VERSION 5.8 ;
BUSBITCHARS "[]" ;
DIVIDERCHAR "/" ;
UNITS
    DATABASE MICRONS 1000 ;
END UNITS

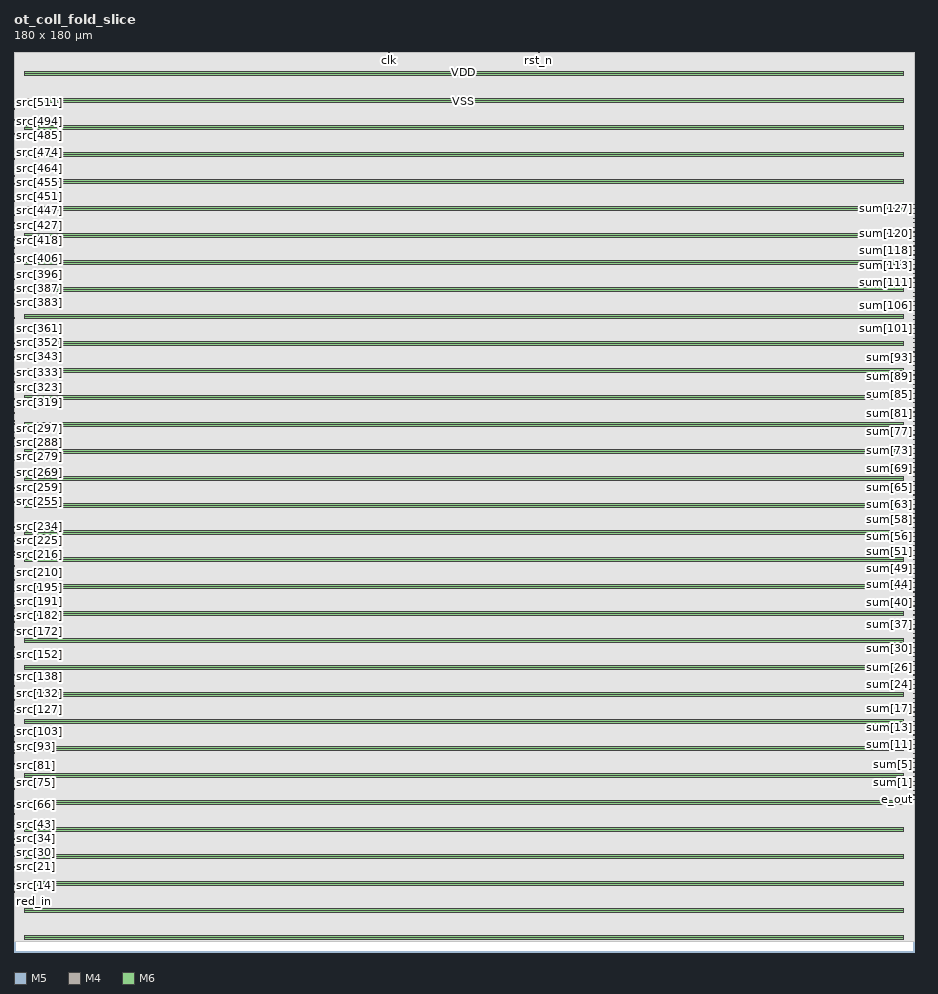
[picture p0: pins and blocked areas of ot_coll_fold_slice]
MACRO ot_coll_fold_slice
  FOREIGN ot_coll_fold_slice 0 0 ;
  CLASS BLOCK ;
  SIZE 180 BY 180 ;
  PIN clk
    DIRECTION INPUT ;
    USE SIGNAL ;
    PORT
      LAYER M5 ;
        RECT  74.976 179.916 75 180 ;
    END
  END clk
  PIN e_out
    DIRECTION OUTPUT ;
    USE SIGNAL ;
    PORT
      LAYER M4 ;
        RECT  179.916 30.432 180 30.456 ;
    END
  END e_out
  PIN red_in
    DIRECTION INPUT ;
    USE SIGNAL ;
    PORT
      LAYER M4 ;
        RECT  0 10.128 0.084 10.152 ;
    END
  END red_in
  PIN rst_n
    DIRECTION INPUT ;
    USE SIGNAL ;
    PORT
      LAYER M5 ;
        RECT  104.976 179.916 105 180 ;
    END
  END rst_n
  PIN src[0]
    DIRECTION INPUT ;
    USE SIGNAL ;
    PORT
      LAYER M4 ;
        RECT  0 10.464 0.084 10.488 ;
    END
  END src[0]
  PIN src[100]
    DIRECTION INPUT ;
    USE SIGNAL ;
    PORT
      LAYER M6 ;
        RECT  0 41.664 0.07 41.696 ;
    END
  END src[100]
  PIN src[101]
    DIRECTION INPUT ;
    USE SIGNAL ;
    PORT
      LAYER M6 ;
        RECT  0 41.984 0.07 42.016 ;
    END
  END src[101]
  PIN src[102]
    DIRECTION INPUT ;
    USE SIGNAL ;
    PORT
      LAYER M6 ;
        RECT  0 42.24 0.07 42.272 ;
    END
  END src[102]
  PIN src[103]
    DIRECTION INPUT ;
    USE SIGNAL ;
    PORT
      LAYER M6 ;
        RECT  0 42.56 0.07 42.592 ;
    END
  END src[103]
  PIN src[104]
    DIRECTION INPUT ;
    USE SIGNAL ;
    PORT
      LAYER M6 ;
        RECT  0 42.88 0.07 42.912 ;
    END
  END src[104]
  PIN src[105]
    DIRECTION INPUT ;
    USE SIGNAL ;
    PORT
      LAYER M6 ;
        RECT  0 43.2 0.07 43.232 ;
    END
  END src[105]
  PIN src[106]
    DIRECTION INPUT ;
    USE SIGNAL ;
    PORT
      LAYER M6 ;
        RECT  0 43.52 0.07 43.552 ;
    END
  END src[106]
  PIN src[107]
    DIRECTION INPUT ;
    USE SIGNAL ;
    PORT
      LAYER M6 ;
        RECT  0 43.84 0.07 43.872 ;
    END
  END src[107]
  PIN src[108]
    DIRECTION INPUT ;
    USE SIGNAL ;
    PORT
      LAYER M6 ;
        RECT  0 44.16 0.07 44.192 ;
    END
  END src[108]
  PIN src[109]
    DIRECTION INPUT ;
    USE SIGNAL ;
    PORT
      LAYER M6 ;
        RECT  0 44.48 0.07 44.512 ;
    END
  END src[109]
  PIN src[10]
    DIRECTION INPUT ;
    USE SIGNAL ;
    PORT
      LAYER M4 ;
        RECT  0 13.584 0.084 13.608 ;
    END
  END src[10]
  PIN src[110]
    DIRECTION INPUT ;
    USE SIGNAL ;
    PORT
      LAYER M6 ;
        RECT  0 44.736 0.07 44.768 ;
    END
  END src[110]
  PIN src[111]
    DIRECTION INPUT ;
    USE SIGNAL ;
    PORT
      LAYER M6 ;
        RECT  0 45.056 0.07 45.088 ;
    END
  END src[111]
  PIN src[112]
    DIRECTION INPUT ;
    USE SIGNAL ;
    PORT
      LAYER M6 ;
        RECT  0 45.376 0.07 45.408 ;
    END
  END src[112]
  PIN src[113]
    DIRECTION INPUT ;
    USE SIGNAL ;
    PORT
      LAYER M6 ;
        RECT  0 45.696 0.07 45.728 ;
    END
  END src[113]
  PIN src[114]
    DIRECTION INPUT ;
    USE SIGNAL ;
    PORT
      LAYER M6 ;
        RECT  0 46.016 0.07 46.048 ;
    END
  END src[114]
  PIN src[115]
    DIRECTION INPUT ;
    USE SIGNAL ;
    PORT
      LAYER M6 ;
        RECT  0 46.336 0.07 46.368 ;
    END
  END src[115]
  PIN src[116]
    DIRECTION INPUT ;
    USE SIGNAL ;
    PORT
      LAYER M6 ;
        RECT  0 46.656 0.07 46.688 ;
    END
  END src[116]
  PIN src[117]
    DIRECTION INPUT ;
    USE SIGNAL ;
    PORT
      LAYER M6 ;
        RECT  0 46.912 0.07 46.944 ;
    END
  END src[117]
  PIN src[118]
    DIRECTION INPUT ;
    USE SIGNAL ;
    PORT
      LAYER M6 ;
        RECT  0 47.232 0.07 47.264 ;
    END
  END src[118]
  PIN src[119]
    DIRECTION INPUT ;
    USE SIGNAL ;
    PORT
      LAYER M6 ;
        RECT  0 47.552 0.07 47.584 ;
    END
  END src[119]
  PIN src[11]
    DIRECTION INPUT ;
    USE SIGNAL ;
    PORT
      LAYER M4 ;
        RECT  0 13.872 0.084 13.896 ;
    END
  END src[11]
  PIN src[120]
    DIRECTION INPUT ;
    USE SIGNAL ;
    PORT
      LAYER M6 ;
        RECT  0 47.872 0.07 47.904 ;
    END
  END src[120]
  PIN src[121]
    DIRECTION INPUT ;
    USE SIGNAL ;
    PORT
      LAYER M6 ;
        RECT  0 48.192 0.07 48.224 ;
    END
  END src[121]
  PIN src[122]
    DIRECTION INPUT ;
    USE SIGNAL ;
    PORT
      LAYER M6 ;
        RECT  0 48.512 0.07 48.544 ;
    END
  END src[122]
  PIN src[123]
    DIRECTION INPUT ;
    USE SIGNAL ;
    PORT
      LAYER M6 ;
        RECT  0 48.832 0.07 48.864 ;
    END
  END src[123]
  PIN src[124]
    DIRECTION INPUT ;
    USE SIGNAL ;
    PORT
      LAYER M6 ;
        RECT  0 49.152 0.07 49.184 ;
    END
  END src[124]
  PIN src[125]
    DIRECTION INPUT ;
    USE SIGNAL ;
    PORT
      LAYER M6 ;
        RECT  0 49.408 0.07 49.44 ;
    END
  END src[125]
  PIN src[126]
    DIRECTION INPUT ;
    USE SIGNAL ;
    PORT
      LAYER M6 ;
        RECT  0 49.728 0.07 49.76 ;
    END
  END src[126]
  PIN src[127]
    DIRECTION INPUT ;
    USE SIGNAL ;
    PORT
      LAYER M4 ;
        RECT  0 50.064 0.084 50.088 ;
    END
  END src[127]
  PIN src[128]
    DIRECTION INPUT ;
    USE SIGNAL ;
    PORT
      LAYER M4 ;
        RECT  0 50.4 0.084 50.424 ;
    END
  END src[128]
  PIN src[129]
    DIRECTION INPUT ;
    USE SIGNAL ;
    PORT
      LAYER M4 ;
        RECT  0 50.688 0.084 50.712 ;
    END
  END src[129]
  PIN src[12]
    DIRECTION INPUT ;
    USE SIGNAL ;
    PORT
      LAYER M4 ;
        RECT  0 14.208 0.084 14.232 ;
    END
  END src[12]
  PIN src[130]
    DIRECTION INPUT ;
    USE SIGNAL ;
    PORT
      LAYER M4 ;
        RECT  0 51.024 0.084 51.048 ;
    END
  END src[130]
  PIN src[131]
    DIRECTION INPUT ;
    USE SIGNAL ;
    PORT
      LAYER M4 ;
        RECT  0 51.312 0.084 51.336 ;
    END
  END src[131]
  PIN src[132]
    DIRECTION INPUT ;
    USE SIGNAL ;
    PORT
      LAYER M4 ;
        RECT  0 51.648 0.084 51.672 ;
    END
  END src[132]
  PIN src[133]
    DIRECTION INPUT ;
    USE SIGNAL ;
    PORT
      LAYER M4 ;
        RECT  0 51.936 0.084 51.96 ;
    END
  END src[133]
  PIN src[134]
    DIRECTION INPUT ;
    USE SIGNAL ;
    PORT
      LAYER M4 ;
        RECT  0 52.272 0.084 52.296 ;
    END
  END src[134]
  PIN src[135]
    DIRECTION INPUT ;
    USE SIGNAL ;
    PORT
      LAYER M4 ;
        RECT  0 52.56 0.084 52.584 ;
    END
  END src[135]
  PIN src[136]
    DIRECTION INPUT ;
    USE SIGNAL ;
    PORT
      LAYER M4 ;
        RECT  0 52.896 0.084 52.92 ;
    END
  END src[136]
  PIN src[137]
    DIRECTION INPUT ;
    USE SIGNAL ;
    PORT
      LAYER M4 ;
        RECT  0 53.184 0.084 53.208 ;
    END
  END src[137]
  PIN src[138]
    DIRECTION INPUT ;
    USE SIGNAL ;
    PORT
      LAYER M4 ;
        RECT  0 53.52 0.084 53.544 ;
    END
  END src[138]
  PIN src[139]
    DIRECTION INPUT ;
    USE SIGNAL ;
    PORT
      LAYER M4 ;
        RECT  0 53.808 0.084 53.832 ;
    END
  END src[139]
  PIN src[13]
    DIRECTION INPUT ;
    USE SIGNAL ;
    PORT
      LAYER M4 ;
        RECT  0 14.496 0.084 14.52 ;
    END
  END src[13]
  PIN src[140]
    DIRECTION INPUT ;
    USE SIGNAL ;
    PORT
      LAYER M4 ;
        RECT  0 54.144 0.084 54.168 ;
    END
  END src[140]
  PIN src[141]
    DIRECTION INPUT ;
    USE SIGNAL ;
    PORT
      LAYER M4 ;
        RECT  0 54.432 0.084 54.456 ;
    END
  END src[141]
  PIN src[142]
    DIRECTION INPUT ;
    USE SIGNAL ;
    PORT
      LAYER M4 ;
        RECT  0 54.768 0.084 54.792 ;
    END
  END src[142]
  PIN src[143]
    DIRECTION INPUT ;
    USE SIGNAL ;
    PORT
      LAYER M4 ;
        RECT  0 55.056 0.084 55.08 ;
    END
  END src[143]
  PIN src[144]
    DIRECTION INPUT ;
    USE SIGNAL ;
    PORT
      LAYER M4 ;
        RECT  0 55.392 0.084 55.416 ;
    END
  END src[144]
  PIN src[145]
    DIRECTION INPUT ;
    USE SIGNAL ;
    PORT
      LAYER M4 ;
        RECT  0 55.68 0.084 55.704 ;
    END
  END src[145]
  PIN src[146]
    DIRECTION INPUT ;
    USE SIGNAL ;
    PORT
      LAYER M4 ;
        RECT  0 56.016 0.084 56.04 ;
    END
  END src[146]
  PIN src[147]
    DIRECTION INPUT ;
    USE SIGNAL ;
    PORT
      LAYER M4 ;
        RECT  0 56.304 0.084 56.328 ;
    END
  END src[147]
  PIN src[148]
    DIRECTION INPUT ;
    USE SIGNAL ;
    PORT
      LAYER M4 ;
        RECT  0 56.64 0.084 56.664 ;
    END
  END src[148]
  PIN src[149]
    DIRECTION INPUT ;
    USE SIGNAL ;
    PORT
      LAYER M4 ;
        RECT  0 56.928 0.084 56.952 ;
    END
  END src[149]
  PIN src[14]
    DIRECTION INPUT ;
    USE SIGNAL ;
    PORT
      LAYER M4 ;
        RECT  0 14.832 0.084 14.856 ;
    END
  END src[14]
  PIN src[150]
    DIRECTION INPUT ;
    USE SIGNAL ;
    PORT
      LAYER M4 ;
        RECT  0 57.216 0.084 57.24 ;
    END
  END src[150]
  PIN src[151]
    DIRECTION INPUT ;
    USE SIGNAL ;
    PORT
      LAYER M4 ;
        RECT  0 57.552 0.084 57.576 ;
    END
  END src[151]
  PIN src[152]
    DIRECTION INPUT ;
    USE SIGNAL ;
    PORT
      LAYER M4 ;
        RECT  0 57.84 0.084 57.864 ;
    END
  END src[152]
  PIN src[153]
    DIRECTION INPUT ;
    USE SIGNAL ;
    PORT
      LAYER M4 ;
        RECT  0 58.176 0.084 58.2 ;
    END
  END src[153]
  PIN src[154]
    DIRECTION INPUT ;
    USE SIGNAL ;
    PORT
      LAYER M4 ;
        RECT  0 58.464 0.084 58.488 ;
    END
  END src[154]
  PIN src[155]
    DIRECTION INPUT ;
    USE SIGNAL ;
    PORT
      LAYER M4 ;
        RECT  0 58.8 0.084 58.824 ;
    END
  END src[155]
  PIN src[156]
    DIRECTION INPUT ;
    USE SIGNAL ;
    PORT
      LAYER M4 ;
        RECT  0 59.088 0.084 59.112 ;
    END
  END src[156]
  PIN src[157]
    DIRECTION INPUT ;
    USE SIGNAL ;
    PORT
      LAYER M4 ;
        RECT  0 59.424 0.084 59.448 ;
    END
  END src[157]
  PIN src[158]
    DIRECTION INPUT ;
    USE SIGNAL ;
    PORT
      LAYER M4 ;
        RECT  0 59.712 0.084 59.736 ;
    END
  END src[158]
  PIN src[159]
    DIRECTION INPUT ;
    USE SIGNAL ;
    PORT
      LAYER M6 ;
        RECT  0 60.032 0.07 60.064 ;
    END
  END src[159]
  PIN src[15]
    DIRECTION INPUT ;
    USE SIGNAL ;
    PORT
      LAYER M4 ;
        RECT  0 15.12 0.084 15.144 ;
    END
  END src[15]
  PIN src[160]
    DIRECTION INPUT ;
    USE SIGNAL ;
    PORT
      LAYER M6 ;
        RECT  0 60.352 0.07 60.384 ;
    END
  END src[160]
  PIN src[161]
    DIRECTION INPUT ;
    USE SIGNAL ;
    PORT
      LAYER M6 ;
        RECT  0 60.672 0.07 60.704 ;
    END
  END src[161]
  PIN src[162]
    DIRECTION INPUT ;
    USE SIGNAL ;
    PORT
      LAYER M6 ;
        RECT  0 60.992 0.07 61.024 ;
    END
  END src[162]
  PIN src[163]
    DIRECTION INPUT ;
    USE SIGNAL ;
    PORT
      LAYER M6 ;
        RECT  0 61.312 0.07 61.344 ;
    END
  END src[163]
  PIN src[164]
    DIRECTION INPUT ;
    USE SIGNAL ;
    PORT
      LAYER M6 ;
        RECT  0 61.632 0.07 61.664 ;
    END
  END src[164]
  PIN src[165]
    DIRECTION INPUT ;
    USE SIGNAL ;
    PORT
      LAYER M6 ;
        RECT  0 61.888 0.07 61.92 ;
    END
  END src[165]
  PIN src[166]
    DIRECTION INPUT ;
    USE SIGNAL ;
    PORT
      LAYER M6 ;
        RECT  0 62.208 0.07 62.24 ;
    END
  END src[166]
  PIN src[167]
    DIRECTION INPUT ;
    USE SIGNAL ;
    PORT
      LAYER M6 ;
        RECT  0 62.528 0.07 62.56 ;
    END
  END src[167]
  PIN src[168]
    DIRECTION INPUT ;
    USE SIGNAL ;
    PORT
      LAYER M6 ;
        RECT  0 62.848 0.07 62.88 ;
    END
  END src[168]
  PIN src[169]
    DIRECTION INPUT ;
    USE SIGNAL ;
    PORT
      LAYER M6 ;
        RECT  0 63.168 0.07 63.2 ;
    END
  END src[169]
  PIN src[16]
    DIRECTION INPUT ;
    USE SIGNAL ;
    PORT
      LAYER M4 ;
        RECT  0 15.456 0.084 15.48 ;
    END
  END src[16]
  PIN src[170]
    DIRECTION INPUT ;
    USE SIGNAL ;
    PORT
      LAYER M6 ;
        RECT  0 63.488 0.07 63.52 ;
    END
  END src[170]
  PIN src[171]
    DIRECTION INPUT ;
    USE SIGNAL ;
    PORT
      LAYER M6 ;
        RECT  0 63.808 0.07 63.84 ;
    END
  END src[171]
  PIN src[172]
    DIRECTION INPUT ;
    USE SIGNAL ;
    PORT
      LAYER M6 ;
        RECT  0 64.128 0.07 64.16 ;
    END
  END src[172]
  PIN src[173]
    DIRECTION INPUT ;
    USE SIGNAL ;
    PORT
      LAYER M6 ;
        RECT  0 64.384 0.07 64.416 ;
    END
  END src[173]
  PIN src[174]
    DIRECTION INPUT ;
    USE SIGNAL ;
    PORT
      LAYER M6 ;
        RECT  0 64.704 0.07 64.736 ;
    END
  END src[174]
  PIN src[175]
    DIRECTION INPUT ;
    USE SIGNAL ;
    PORT
      LAYER M6 ;
        RECT  0 65.024 0.07 65.056 ;
    END
  END src[175]
  PIN src[176]
    DIRECTION INPUT ;
    USE SIGNAL ;
    PORT
      LAYER M6 ;
        RECT  0 65.344 0.07 65.376 ;
    END
  END src[176]
  PIN src[177]
    DIRECTION INPUT ;
    USE SIGNAL ;
    PORT
      LAYER M6 ;
        RECT  0 65.664 0.07 65.696 ;
    END
  END src[177]
  PIN src[178]
    DIRECTION INPUT ;
    USE SIGNAL ;
    PORT
      LAYER M6 ;
        RECT  0 65.984 0.07 66.016 ;
    END
  END src[178]
  PIN src[179]
    DIRECTION INPUT ;
    USE SIGNAL ;
    PORT
      LAYER M6 ;
        RECT  0 66.304 0.07 66.336 ;
    END
  END src[179]
  PIN src[17]
    DIRECTION INPUT ;
    USE SIGNAL ;
    PORT
      LAYER M4 ;
        RECT  0 15.744 0.084 15.768 ;
    END
  END src[17]
  PIN src[180]
    DIRECTION INPUT ;
    USE SIGNAL ;
    PORT
      LAYER M6 ;
        RECT  0 66.624 0.07 66.656 ;
    END
  END src[180]
  PIN src[181]
    DIRECTION INPUT ;
    USE SIGNAL ;
    PORT
      LAYER M6 ;
        RECT  0 66.88 0.07 66.912 ;
    END
  END src[181]
  PIN src[182]
    DIRECTION INPUT ;
    USE SIGNAL ;
    PORT
      LAYER M6 ;
        RECT  0 67.2 0.07 67.232 ;
    END
  END src[182]
  PIN src[183]
    DIRECTION INPUT ;
    USE SIGNAL ;
    PORT
      LAYER M6 ;
        RECT  0 67.52 0.07 67.552 ;
    END
  END src[183]
  PIN src[184]
    DIRECTION INPUT ;
    USE SIGNAL ;
    PORT
      LAYER M6 ;
        RECT  0 67.84 0.07 67.872 ;
    END
  END src[184]
  PIN src[185]
    DIRECTION INPUT ;
    USE SIGNAL ;
    PORT
      LAYER M6 ;
        RECT  0 68.16 0.07 68.192 ;
    END
  END src[185]
  PIN src[186]
    DIRECTION INPUT ;
    USE SIGNAL ;
    PORT
      LAYER M6 ;
        RECT  0 68.48 0.07 68.512 ;
    END
  END src[186]
  PIN src[187]
    DIRECTION INPUT ;
    USE SIGNAL ;
    PORT
      LAYER M6 ;
        RECT  0 68.8 0.07 68.832 ;
    END
  END src[187]
  PIN src[188]
    DIRECTION INPUT ;
    USE SIGNAL ;
    PORT
      LAYER M6 ;
        RECT  0 69.056 0.07 69.088 ;
    END
  END src[188]
  PIN src[189]
    DIRECTION INPUT ;
    USE SIGNAL ;
    PORT
      LAYER M6 ;
        RECT  0 69.376 0.07 69.408 ;
    END
  END src[189]
  PIN src[18]
    DIRECTION INPUT ;
    USE SIGNAL ;
    PORT
      LAYER M4 ;
        RECT  0 16.08 0.084 16.104 ;
    END
  END src[18]
  PIN src[190]
    DIRECTION INPUT ;
    USE SIGNAL ;
    PORT
      LAYER M6 ;
        RECT  0 69.696 0.07 69.728 ;
    END
  END src[190]
  PIN src[191]
    DIRECTION INPUT ;
    USE SIGNAL ;
    PORT
      LAYER M4 ;
        RECT  0 70.032 0.084 70.056 ;
    END
  END src[191]
  PIN src[192]
    DIRECTION INPUT ;
    USE SIGNAL ;
    PORT
      LAYER M4 ;
        RECT  0 70.32 0.084 70.344 ;
    END
  END src[192]
  PIN src[193]
    DIRECTION INPUT ;
    USE SIGNAL ;
    PORT
      LAYER M4 ;
        RECT  0 70.656 0.084 70.68 ;
    END
  END src[193]
  PIN src[194]
    DIRECTION INPUT ;
    USE SIGNAL ;
    PORT
      LAYER M4 ;
        RECT  0 70.944 0.084 70.968 ;
    END
  END src[194]
  PIN src[195]
    DIRECTION INPUT ;
    USE SIGNAL ;
    PORT
      LAYER M4 ;
        RECT  0 71.28 0.084 71.304 ;
    END
  END src[195]
  PIN src[196]
    DIRECTION INPUT ;
    USE SIGNAL ;
    PORT
      LAYER M4 ;
        RECT  0 71.568 0.084 71.592 ;
    END
  END src[196]
  PIN src[197]
    DIRECTION INPUT ;
    USE SIGNAL ;
    PORT
      LAYER M4 ;
        RECT  0 71.904 0.084 71.928 ;
    END
  END src[197]
  PIN src[198]
    DIRECTION INPUT ;
    USE SIGNAL ;
    PORT
      LAYER M4 ;
        RECT  0 72.192 0.084 72.216 ;
    END
  END src[198]
  PIN src[199]
    DIRECTION INPUT ;
    USE SIGNAL ;
    PORT
      LAYER M4 ;
        RECT  0 72.528 0.084 72.552 ;
    END
  END src[199]
  PIN src[19]
    DIRECTION INPUT ;
    USE SIGNAL ;
    PORT
      LAYER M4 ;
        RECT  0 16.368 0.084 16.392 ;
    END
  END src[19]
  PIN src[1]
    DIRECTION INPUT ;
    USE SIGNAL ;
    PORT
      LAYER M4 ;
        RECT  0 10.752 0.084 10.776 ;
    END
  END src[1]
  PIN src[200]
    DIRECTION INPUT ;
    USE SIGNAL ;
    PORT
      LAYER M4 ;
        RECT  0 72.816 0.084 72.84 ;
    END
  END src[200]
  PIN src[201]
    DIRECTION INPUT ;
    USE SIGNAL ;
    PORT
      LAYER M4 ;
        RECT  0 73.152 0.084 73.176 ;
    END
  END src[201]
  PIN src[202]
    DIRECTION INPUT ;
    USE SIGNAL ;
    PORT
      LAYER M4 ;
        RECT  0 73.44 0.084 73.464 ;
    END
  END src[202]
  PIN src[203]
    DIRECTION INPUT ;
    USE SIGNAL ;
    PORT
      LAYER M4 ;
        RECT  0 73.776 0.084 73.8 ;
    END
  END src[203]
  PIN src[204]
    DIRECTION INPUT ;
    USE SIGNAL ;
    PORT
      LAYER M4 ;
        RECT  0 74.064 0.084 74.088 ;
    END
  END src[204]
  PIN src[205]
    DIRECTION INPUT ;
    USE SIGNAL ;
    PORT
      LAYER M4 ;
        RECT  0 74.4 0.084 74.424 ;
    END
  END src[205]
  PIN src[206]
    DIRECTION INPUT ;
    USE SIGNAL ;
    PORT
      LAYER M4 ;
        RECT  0 74.688 0.084 74.712 ;
    END
  END src[206]
  PIN src[207]
    DIRECTION INPUT ;
    USE SIGNAL ;
    PORT
      LAYER M4 ;
        RECT  0 75.024 0.084 75.048 ;
    END
  END src[207]
  PIN src[208]
    DIRECTION INPUT ;
    USE SIGNAL ;
    PORT
      LAYER M4 ;
        RECT  0 75.312 0.084 75.336 ;
    END
  END src[208]
  PIN src[209]
    DIRECTION INPUT ;
    USE SIGNAL ;
    PORT
      LAYER M4 ;
        RECT  0 75.648 0.084 75.672 ;
    END
  END src[209]
  PIN src[20]
    DIRECTION INPUT ;
    USE SIGNAL ;
    PORT
      LAYER M4 ;
        RECT  0 16.704 0.084 16.728 ;
    END
  END src[20]
  PIN src[210]
    DIRECTION INPUT ;
    USE SIGNAL ;
    PORT
      LAYER M4 ;
        RECT  0 75.936 0.084 75.96 ;
    END
  END src[210]
  PIN src[211]
    DIRECTION INPUT ;
    USE SIGNAL ;
    PORT
      LAYER M4 ;
        RECT  0 76.272 0.084 76.296 ;
    END
  END src[211]
  PIN src[212]
    DIRECTION INPUT ;
    USE SIGNAL ;
    PORT
      LAYER M4 ;
        RECT  0 76.56 0.084 76.584 ;
    END
  END src[212]
  PIN src[213]
    DIRECTION INPUT ;
    USE SIGNAL ;
    PORT
      LAYER M4 ;
        RECT  0 76.896 0.084 76.92 ;
    END
  END src[213]
  PIN src[214]
    DIRECTION INPUT ;
    USE SIGNAL ;
    PORT
      LAYER M4 ;
        RECT  0 77.184 0.084 77.208 ;
    END
  END src[214]
  PIN src[215]
    DIRECTION INPUT ;
    USE SIGNAL ;
    PORT
      LAYER M4 ;
        RECT  0 77.52 0.084 77.544 ;
    END
  END src[215]
  PIN src[216]
    DIRECTION INPUT ;
    USE SIGNAL ;
    PORT
      LAYER M4 ;
        RECT  0 77.808 0.084 77.832 ;
    END
  END src[216]
  PIN src[217]
    DIRECTION INPUT ;
    USE SIGNAL ;
    PORT
      LAYER M4 ;
        RECT  0 78.144 0.084 78.168 ;
    END
  END src[217]
  PIN src[218]
    DIRECTION INPUT ;
    USE SIGNAL ;
    PORT
      LAYER M4 ;
        RECT  0 78.432 0.084 78.456 ;
    END
  END src[218]
  PIN src[219]
    DIRECTION INPUT ;
    USE SIGNAL ;
    PORT
      LAYER M4 ;
        RECT  0 78.768 0.084 78.792 ;
    END
  END src[219]
  PIN src[21]
    DIRECTION INPUT ;
    USE SIGNAL ;
    PORT
      LAYER M4 ;
        RECT  0 16.992 0.084 17.016 ;
    END
  END src[21]
  PIN src[220]
    DIRECTION INPUT ;
    USE SIGNAL ;
    PORT
      LAYER M4 ;
        RECT  0 79.056 0.084 79.08 ;
    END
  END src[220]
  PIN src[221]
    DIRECTION INPUT ;
    USE SIGNAL ;
    PORT
      LAYER M4 ;
        RECT  0 79.392 0.084 79.416 ;
    END
  END src[221]
  PIN src[222]
    DIRECTION INPUT ;
    USE SIGNAL ;
    PORT
      LAYER M4 ;
        RECT  0 79.68 0.084 79.704 ;
    END
  END src[222]
  PIN src[223]
    DIRECTION INPUT ;
    USE SIGNAL ;
    PORT
      LAYER M6 ;
        RECT  0 80 0.07 80.032 ;
    END
  END src[223]
  PIN src[224]
    DIRECTION INPUT ;
    USE SIGNAL ;
    PORT
      LAYER M6 ;
        RECT  0 80.32 0.07 80.352 ;
    END
  END src[224]
  PIN src[225]
    DIRECTION INPUT ;
    USE SIGNAL ;
    PORT
      LAYER M6 ;
        RECT  0 80.64 0.07 80.672 ;
    END
  END src[225]
  PIN src[226]
    DIRECTION INPUT ;
    USE SIGNAL ;
    PORT
      LAYER M6 ;
        RECT  0 80.96 0.07 80.992 ;
    END
  END src[226]
  PIN src[227]
    DIRECTION INPUT ;
    USE SIGNAL ;
    PORT
      LAYER M6 ;
        RECT  0 81.28 0.07 81.312 ;
    END
  END src[227]
  PIN src[228]
    DIRECTION INPUT ;
    USE SIGNAL ;
    PORT
      LAYER M6 ;
        RECT  0 81.536 0.07 81.568 ;
    END
  END src[228]
  PIN src[229]
    DIRECTION INPUT ;
    USE SIGNAL ;
    PORT
      LAYER M6 ;
        RECT  0 81.856 0.07 81.888 ;
    END
  END src[229]
  PIN src[22]
    DIRECTION INPUT ;
    USE SIGNAL ;
    PORT
      LAYER M4 ;
        RECT  0 17.328 0.084 17.352 ;
    END
  END src[22]
  PIN src[230]
    DIRECTION INPUT ;
    USE SIGNAL ;
    PORT
      LAYER M6 ;
        RECT  0 82.176 0.07 82.208 ;
    END
  END src[230]
  PIN src[231]
    DIRECTION INPUT ;
    USE SIGNAL ;
    PORT
      LAYER M6 ;
        RECT  0 82.496 0.07 82.528 ;
    END
  END src[231]
  PIN src[232]
    DIRECTION INPUT ;
    USE SIGNAL ;
    PORT
      LAYER M6 ;
        RECT  0 82.816 0.07 82.848 ;
    END
  END src[232]
  PIN src[233]
    DIRECTION INPUT ;
    USE SIGNAL ;
    PORT
      LAYER M6 ;
        RECT  0 83.136 0.07 83.168 ;
    END
  END src[233]
  PIN src[234]
    DIRECTION INPUT ;
    USE SIGNAL ;
    PORT
      LAYER M6 ;
        RECT  0 83.456 0.07 83.488 ;
    END
  END src[234]
  PIN src[235]
    DIRECTION INPUT ;
    USE SIGNAL ;
    PORT
      LAYER M6 ;
        RECT  0 83.776 0.07 83.808 ;
    END
  END src[235]
  PIN src[236]
    DIRECTION INPUT ;
    USE SIGNAL ;
    PORT
      LAYER M6 ;
        RECT  0 84.032 0.07 84.064 ;
    END
  END src[236]
  PIN src[237]
    DIRECTION INPUT ;
    USE SIGNAL ;
    PORT
      LAYER M6 ;
        RECT  0 84.352 0.07 84.384 ;
    END
  END src[237]
  PIN src[238]
    DIRECTION INPUT ;
    USE SIGNAL ;
    PORT
      LAYER M6 ;
        RECT  0 84.672 0.07 84.704 ;
    END
  END src[238]
  PIN src[239]
    DIRECTION INPUT ;
    USE SIGNAL ;
    PORT
      LAYER M6 ;
        RECT  0 84.992 0.07 85.024 ;
    END
  END src[239]
  PIN src[23]
    DIRECTION INPUT ;
    USE SIGNAL ;
    PORT
      LAYER M4 ;
        RECT  0 17.616 0.084 17.64 ;
    END
  END src[23]
  PIN src[240]
    DIRECTION INPUT ;
    USE SIGNAL ;
    PORT
      LAYER M6 ;
        RECT  0 85.312 0.07 85.344 ;
    END
  END src[240]
  PIN src[241]
    DIRECTION INPUT ;
    USE SIGNAL ;
    PORT
      LAYER M6 ;
        RECT  0 85.632 0.07 85.664 ;
    END
  END src[241]
  PIN src[242]
    DIRECTION INPUT ;
    USE SIGNAL ;
    PORT
      LAYER M6 ;
        RECT  0 85.952 0.07 85.984 ;
    END
  END src[242]
  PIN src[243]
    DIRECTION INPUT ;
    USE SIGNAL ;
    PORT
      LAYER M6 ;
        RECT  0 86.272 0.07 86.304 ;
    END
  END src[243]
  PIN src[244]
    DIRECTION INPUT ;
    USE SIGNAL ;
    PORT
      LAYER M6 ;
        RECT  0 86.528 0.07 86.56 ;
    END
  END src[244]
  PIN src[245]
    DIRECTION INPUT ;
    USE SIGNAL ;
    PORT
      LAYER M6 ;
        RECT  0 86.848 0.07 86.88 ;
    END
  END src[245]
  PIN src[246]
    DIRECTION INPUT ;
    USE SIGNAL ;
    PORT
      LAYER M6 ;
        RECT  0 87.168 0.07 87.2 ;
    END
  END src[246]
  PIN src[247]
    DIRECTION INPUT ;
    USE SIGNAL ;
    PORT
      LAYER M6 ;
        RECT  0 87.488 0.07 87.52 ;
    END
  END src[247]
  PIN src[248]
    DIRECTION INPUT ;
    USE SIGNAL ;
    PORT
      LAYER M6 ;
        RECT  0 87.808 0.07 87.84 ;
    END
  END src[248]
  PIN src[249]
    DIRECTION INPUT ;
    USE SIGNAL ;
    PORT
      LAYER M6 ;
        RECT  0 88.128 0.07 88.16 ;
    END
  END src[249]
  PIN src[24]
    DIRECTION INPUT ;
    USE SIGNAL ;
    PORT
      LAYER M4 ;
        RECT  0 17.952 0.084 17.976 ;
    END
  END src[24]
  PIN src[250]
    DIRECTION INPUT ;
    USE SIGNAL ;
    PORT
      LAYER M6 ;
        RECT  0 88.448 0.07 88.48 ;
    END
  END src[250]
  PIN src[251]
    DIRECTION INPUT ;
    USE SIGNAL ;
    PORT
      LAYER M6 ;
        RECT  0 88.768 0.07 88.8 ;
    END
  END src[251]
  PIN src[252]
    DIRECTION INPUT ;
    USE SIGNAL ;
    PORT
      LAYER M6 ;
        RECT  0 89.024 0.07 89.056 ;
    END
  END src[252]
  PIN src[253]
    DIRECTION INPUT ;
    USE SIGNAL ;
    PORT
      LAYER M6 ;
        RECT  0 89.344 0.07 89.376 ;
    END
  END src[253]
  PIN src[254]
    DIRECTION INPUT ;
    USE SIGNAL ;
    PORT
      LAYER M6 ;
        RECT  0 89.664 0.07 89.696 ;
    END
  END src[254]
  PIN src[255]
    DIRECTION INPUT ;
    USE SIGNAL ;
    PORT
      LAYER M4 ;
        RECT  0 90 0.084 90.024 ;
    END
  END src[255]
  PIN src[256]
    DIRECTION INPUT ;
    USE SIGNAL ;
    PORT
      LAYER M4 ;
        RECT  0 90.288 0.084 90.312 ;
    END
  END src[256]
  PIN src[257]
    DIRECTION INPUT ;
    USE SIGNAL ;
    PORT
      LAYER M4 ;
        RECT  0 90.624 0.084 90.648 ;
    END
  END src[257]
  PIN src[258]
    DIRECTION INPUT ;
    USE SIGNAL ;
    PORT
      LAYER M4 ;
        RECT  0 90.912 0.084 90.936 ;
    END
  END src[258]
  PIN src[259]
    DIRECTION INPUT ;
    USE SIGNAL ;
    PORT
      LAYER M4 ;
        RECT  0 91.248 0.084 91.272 ;
    END
  END src[259]
  PIN src[25]
    DIRECTION INPUT ;
    USE SIGNAL ;
    PORT
      LAYER M4 ;
        RECT  0 18.24 0.084 18.264 ;
    END
  END src[25]
  PIN src[260]
    DIRECTION INPUT ;
    USE SIGNAL ;
    PORT
      LAYER M4 ;
        RECT  0 91.536 0.084 91.56 ;
    END
  END src[260]
  PIN src[261]
    DIRECTION INPUT ;
    USE SIGNAL ;
    PORT
      LAYER M4 ;
        RECT  0 91.872 0.084 91.896 ;
    END
  END src[261]
  PIN src[262]
    DIRECTION INPUT ;
    USE SIGNAL ;
    PORT
      LAYER M4 ;
        RECT  0 92.16 0.084 92.184 ;
    END
  END src[262]
  PIN src[263]
    DIRECTION INPUT ;
    USE SIGNAL ;
    PORT
      LAYER M4 ;
        RECT  0 92.496 0.084 92.52 ;
    END
  END src[263]
  PIN src[264]
    DIRECTION INPUT ;
    USE SIGNAL ;
    PORT
      LAYER M4 ;
        RECT  0 92.784 0.084 92.808 ;
    END
  END src[264]
  PIN src[265]
    DIRECTION INPUT ;
    USE SIGNAL ;
    PORT
      LAYER M4 ;
        RECT  0 93.12 0.084 93.144 ;
    END
  END src[265]
  PIN src[266]
    DIRECTION INPUT ;
    USE SIGNAL ;
    PORT
      LAYER M4 ;
        RECT  0 93.408 0.084 93.432 ;
    END
  END src[266]
  PIN src[267]
    DIRECTION INPUT ;
    USE SIGNAL ;
    PORT
      LAYER M4 ;
        RECT  0 93.744 0.084 93.768 ;
    END
  END src[267]
  PIN src[268]
    DIRECTION INPUT ;
    USE SIGNAL ;
    PORT
      LAYER M4 ;
        RECT  0 94.032 0.084 94.056 ;
    END
  END src[268]
  PIN src[269]
    DIRECTION INPUT ;
    USE SIGNAL ;
    PORT
      LAYER M4 ;
        RECT  0 94.368 0.084 94.392 ;
    END
  END src[269]
  PIN src[26]
    DIRECTION INPUT ;
    USE SIGNAL ;
    PORT
      LAYER M4 ;
        RECT  0 18.576 0.084 18.6 ;
    END
  END src[26]
  PIN src[270]
    DIRECTION INPUT ;
    USE SIGNAL ;
    PORT
      LAYER M4 ;
        RECT  0 94.656 0.084 94.68 ;
    END
  END src[270]
  PIN src[271]
    DIRECTION INPUT ;
    USE SIGNAL ;
    PORT
      LAYER M4 ;
        RECT  0 94.992 0.084 95.016 ;
    END
  END src[271]
  PIN src[272]
    DIRECTION INPUT ;
    USE SIGNAL ;
    PORT
      LAYER M4 ;
        RECT  0 95.28 0.084 95.304 ;
    END
  END src[272]
  PIN src[273]
    DIRECTION INPUT ;
    USE SIGNAL ;
    PORT
      LAYER M4 ;
        RECT  0 95.616 0.084 95.64 ;
    END
  END src[273]
  PIN src[274]
    DIRECTION INPUT ;
    USE SIGNAL ;
    PORT
      LAYER M4 ;
        RECT  0 95.904 0.084 95.928 ;
    END
  END src[274]
  PIN src[275]
    DIRECTION INPUT ;
    USE SIGNAL ;
    PORT
      LAYER M4 ;
        RECT  0 96.24 0.084 96.264 ;
    END
  END src[275]
  PIN src[276]
    DIRECTION INPUT ;
    USE SIGNAL ;
    PORT
      LAYER M4 ;
        RECT  0 96.528 0.084 96.552 ;
    END
  END src[276]
  PIN src[277]
    DIRECTION INPUT ;
    USE SIGNAL ;
    PORT
      LAYER M4 ;
        RECT  0 96.864 0.084 96.888 ;
    END
  END src[277]
  PIN src[278]
    DIRECTION INPUT ;
    USE SIGNAL ;
    PORT
      LAYER M4 ;
        RECT  0 97.152 0.084 97.176 ;
    END
  END src[278]
  PIN src[279]
    DIRECTION INPUT ;
    USE SIGNAL ;
    PORT
      LAYER M4 ;
        RECT  0 97.488 0.084 97.512 ;
    END
  END src[279]
  PIN src[27]
    DIRECTION INPUT ;
    USE SIGNAL ;
    PORT
      LAYER M4 ;
        RECT  0 18.864 0.084 18.888 ;
    END
  END src[27]
  PIN src[280]
    DIRECTION INPUT ;
    USE SIGNAL ;
    PORT
      LAYER M4 ;
        RECT  0 97.776 0.084 97.8 ;
    END
  END src[280]
  PIN src[281]
    DIRECTION INPUT ;
    USE SIGNAL ;
    PORT
      LAYER M4 ;
        RECT  0 98.112 0.084 98.136 ;
    END
  END src[281]
  PIN src[282]
    DIRECTION INPUT ;
    USE SIGNAL ;
    PORT
      LAYER M4 ;
        RECT  0 98.4 0.084 98.424 ;
    END
  END src[282]
  PIN src[283]
    DIRECTION INPUT ;
    USE SIGNAL ;
    PORT
      LAYER M4 ;
        RECT  0 98.736 0.084 98.76 ;
    END
  END src[283]
  PIN src[284]
    DIRECTION INPUT ;
    USE SIGNAL ;
    PORT
      LAYER M4 ;
        RECT  0 99.024 0.084 99.048 ;
    END
  END src[284]
  PIN src[285]
    DIRECTION INPUT ;
    USE SIGNAL ;
    PORT
      LAYER M4 ;
        RECT  0 99.36 0.084 99.384 ;
    END
  END src[285]
  PIN src[286]
    DIRECTION INPUT ;
    USE SIGNAL ;
    PORT
      LAYER M4 ;
        RECT  0 99.648 0.084 99.672 ;
    END
  END src[286]
  PIN src[287]
    DIRECTION INPUT ;
    USE SIGNAL ;
    PORT
      LAYER M6 ;
        RECT  0 99.968 0.07 100 ;
    END
  END src[287]
  PIN src[288]
    DIRECTION INPUT ;
    USE SIGNAL ;
    PORT
      LAYER M6 ;
        RECT  0 100.288 0.07 100.32 ;
    END
  END src[288]
  PIN src[289]
    DIRECTION INPUT ;
    USE SIGNAL ;
    PORT
      LAYER M6 ;
        RECT  0 100.608 0.07 100.64 ;
    END
  END src[289]
  PIN src[28]
    DIRECTION INPUT ;
    USE SIGNAL ;
    PORT
      LAYER M4 ;
        RECT  0 19.2 0.084 19.224 ;
    END
  END src[28]
  PIN src[290]
    DIRECTION INPUT ;
    USE SIGNAL ;
    PORT
      LAYER M6 ;
        RECT  0 100.928 0.07 100.96 ;
    END
  END src[290]
  PIN src[291]
    DIRECTION INPUT ;
    USE SIGNAL ;
    PORT
      LAYER M6 ;
        RECT  0 101.184 0.07 101.216 ;
    END
  END src[291]
  PIN src[292]
    DIRECTION INPUT ;
    USE SIGNAL ;
    PORT
      LAYER M6 ;
        RECT  0 101.504 0.07 101.536 ;
    END
  END src[292]
  PIN src[293]
    DIRECTION INPUT ;
    USE SIGNAL ;
    PORT
      LAYER M6 ;
        RECT  0 101.824 0.07 101.856 ;
    END
  END src[293]
  PIN src[294]
    DIRECTION INPUT ;
    USE SIGNAL ;
    PORT
      LAYER M6 ;
        RECT  0 102.144 0.07 102.176 ;
    END
  END src[294]
  PIN src[295]
    DIRECTION INPUT ;
    USE SIGNAL ;
    PORT
      LAYER M6 ;
        RECT  0 102.464 0.07 102.496 ;
    END
  END src[295]
  PIN src[296]
    DIRECTION INPUT ;
    USE SIGNAL ;
    PORT
      LAYER M6 ;
        RECT  0 102.784 0.07 102.816 ;
    END
  END src[296]
  PIN src[297]
    DIRECTION INPUT ;
    USE SIGNAL ;
    PORT
      LAYER M6 ;
        RECT  0 103.104 0.07 103.136 ;
    END
  END src[297]
  PIN src[298]
    DIRECTION INPUT ;
    USE SIGNAL ;
    PORT
      LAYER M6 ;
        RECT  0 103.424 0.07 103.456 ;
    END
  END src[298]
  PIN src[299]
    DIRECTION INPUT ;
    USE SIGNAL ;
    PORT
      LAYER M6 ;
        RECT  0 103.68 0.07 103.712 ;
    END
  END src[299]
  PIN src[29]
    DIRECTION INPUT ;
    USE SIGNAL ;
    PORT
      LAYER M4 ;
        RECT  0 19.488 0.084 19.512 ;
    END
  END src[29]
  PIN src[2]
    DIRECTION INPUT ;
    USE SIGNAL ;
    PORT
      LAYER M4 ;
        RECT  0 11.088 0.084 11.112 ;
    END
  END src[2]
  PIN src[300]
    DIRECTION INPUT ;
    USE SIGNAL ;
    PORT
      LAYER M6 ;
        RECT  0 104 0.07 104.032 ;
    END
  END src[300]
  PIN src[301]
    DIRECTION INPUT ;
    USE SIGNAL ;
    PORT
      LAYER M6 ;
        RECT  0 104.32 0.07 104.352 ;
    END
  END src[301]
  PIN src[302]
    DIRECTION INPUT ;
    USE SIGNAL ;
    PORT
      LAYER M6 ;
        RECT  0 104.64 0.07 104.672 ;
    END
  END src[302]
  PIN src[303]
    DIRECTION INPUT ;
    USE SIGNAL ;
    PORT
      LAYER M6 ;
        RECT  0 104.96 0.07 104.992 ;
    END
  END src[303]
  PIN src[304]
    DIRECTION INPUT ;
    USE SIGNAL ;
    PORT
      LAYER M6 ;
        RECT  0 105.28 0.07 105.312 ;
    END
  END src[304]
  PIN src[305]
    DIRECTION INPUT ;
    USE SIGNAL ;
    PORT
      LAYER M6 ;
        RECT  0 105.6 0.07 105.632 ;
    END
  END src[305]
  PIN src[306]
    DIRECTION INPUT ;
    USE SIGNAL ;
    PORT
      LAYER M6 ;
        RECT  0 105.92 0.07 105.952 ;
    END
  END src[306]
  PIN src[307]
    DIRECTION INPUT ;
    USE SIGNAL ;
    PORT
      LAYER M6 ;
        RECT  0 106.176 0.07 106.208 ;
    END
  END src[307]
  PIN src[308]
    DIRECTION INPUT ;
    USE SIGNAL ;
    PORT
      LAYER M6 ;
        RECT  0 106.496 0.07 106.528 ;
    END
  END src[308]
  PIN src[309]
    DIRECTION INPUT ;
    USE SIGNAL ;
    PORT
      LAYER M6 ;
        RECT  0 106.816 0.07 106.848 ;
    END
  END src[309]
  PIN src[30]
    DIRECTION INPUT ;
    USE SIGNAL ;
    PORT
      LAYER M4 ;
        RECT  0 19.824 0.084 19.848 ;
    END
  END src[30]
  PIN src[310]
    DIRECTION INPUT ;
    USE SIGNAL ;
    PORT
      LAYER M6 ;
        RECT  0 107.136 0.07 107.168 ;
    END
  END src[310]
  PIN src[311]
    DIRECTION INPUT ;
    USE SIGNAL ;
    PORT
      LAYER M6 ;
        RECT  0 107.456 0.07 107.488 ;
    END
  END src[311]
  PIN src[312]
    DIRECTION INPUT ;
    USE SIGNAL ;
    PORT
      LAYER M6 ;
        RECT  0 107.776 0.07 107.808 ;
    END
  END src[312]
  PIN src[313]
    DIRECTION INPUT ;
    USE SIGNAL ;
    PORT
      LAYER M6 ;
        RECT  0 108.096 0.07 108.128 ;
    END
  END src[313]
  PIN src[314]
    DIRECTION INPUT ;
    USE SIGNAL ;
    PORT
      LAYER M6 ;
        RECT  0 108.416 0.07 108.448 ;
    END
  END src[314]
  PIN src[315]
    DIRECTION INPUT ;
    USE SIGNAL ;
    PORT
      LAYER M6 ;
        RECT  0 108.672 0.07 108.704 ;
    END
  END src[315]
  PIN src[316]
    DIRECTION INPUT ;
    USE SIGNAL ;
    PORT
      LAYER M6 ;
        RECT  0 108.992 0.07 109.024 ;
    END
  END src[316]
  PIN src[317]
    DIRECTION INPUT ;
    USE SIGNAL ;
    PORT
      LAYER M6 ;
        RECT  0 109.312 0.07 109.344 ;
    END
  END src[317]
  PIN src[318]
    DIRECTION INPUT ;
    USE SIGNAL ;
    PORT
      LAYER M6 ;
        RECT  0 109.632 0.07 109.664 ;
    END
  END src[318]
  PIN src[319]
    DIRECTION INPUT ;
    USE SIGNAL ;
    PORT
      LAYER M4 ;
        RECT  0 109.968 0.084 109.992 ;
    END
  END src[319]
  PIN src[31]
    DIRECTION INPUT ;
    USE SIGNAL ;
    PORT
      LAYER M6 ;
        RECT  0 20.096 0.07 20.128 ;
    END
  END src[31]
  PIN src[320]
    DIRECTION INPUT ;
    USE SIGNAL ;
    PORT
      LAYER M4 ;
        RECT  0 110.256 0.084 110.28 ;
    END
  END src[320]
  PIN src[321]
    DIRECTION INPUT ;
    USE SIGNAL ;
    PORT
      LAYER M4 ;
        RECT  0 110.592 0.084 110.616 ;
    END
  END src[321]
  PIN src[322]
    DIRECTION INPUT ;
    USE SIGNAL ;
    PORT
      LAYER M4 ;
        RECT  0 110.88 0.084 110.904 ;
    END
  END src[322]
  PIN src[323]
    DIRECTION INPUT ;
    USE SIGNAL ;
    PORT
      LAYER M4 ;
        RECT  0 111.216 0.084 111.24 ;
    END
  END src[323]
  PIN src[324]
    DIRECTION INPUT ;
    USE SIGNAL ;
    PORT
      LAYER M4 ;
        RECT  0 111.504 0.084 111.528 ;
    END
  END src[324]
  PIN src[325]
    DIRECTION INPUT ;
    USE SIGNAL ;
    PORT
      LAYER M4 ;
        RECT  0 111.84 0.084 111.864 ;
    END
  END src[325]
  PIN src[326]
    DIRECTION INPUT ;
    USE SIGNAL ;
    PORT
      LAYER M4 ;
        RECT  0 112.128 0.084 112.152 ;
    END
  END src[326]
  PIN src[327]
    DIRECTION INPUT ;
    USE SIGNAL ;
    PORT
      LAYER M4 ;
        RECT  0 112.464 0.084 112.488 ;
    END
  END src[327]
  PIN src[328]
    DIRECTION INPUT ;
    USE SIGNAL ;
    PORT
      LAYER M4 ;
        RECT  0 112.752 0.084 112.776 ;
    END
  END src[328]
  PIN src[329]
    DIRECTION INPUT ;
    USE SIGNAL ;
    PORT
      LAYER M4 ;
        RECT  0 113.088 0.084 113.112 ;
    END
  END src[329]
  PIN src[32]
    DIRECTION INPUT ;
    USE SIGNAL ;
    PORT
      LAYER M6 ;
        RECT  0 20.416 0.07 20.448 ;
    END
  END src[32]
  PIN src[330]
    DIRECTION INPUT ;
    USE SIGNAL ;
    PORT
      LAYER M4 ;
        RECT  0 113.376 0.084 113.4 ;
    END
  END src[330]
  PIN src[331]
    DIRECTION INPUT ;
    USE SIGNAL ;
    PORT
      LAYER M4 ;
        RECT  0 113.712 0.084 113.736 ;
    END
  END src[331]
  PIN src[332]
    DIRECTION INPUT ;
    USE SIGNAL ;
    PORT
      LAYER M4 ;
        RECT  0 114 0.084 114.024 ;
    END
  END src[332]
  PIN src[333]
    DIRECTION INPUT ;
    USE SIGNAL ;
    PORT
      LAYER M4 ;
        RECT  0 114.336 0.084 114.36 ;
    END
  END src[333]
  PIN src[334]
    DIRECTION INPUT ;
    USE SIGNAL ;
    PORT
      LAYER M4 ;
        RECT  0 114.624 0.084 114.648 ;
    END
  END src[334]
  PIN src[335]
    DIRECTION INPUT ;
    USE SIGNAL ;
    PORT
      LAYER M4 ;
        RECT  0 114.96 0.084 114.984 ;
    END
  END src[335]
  PIN src[336]
    DIRECTION INPUT ;
    USE SIGNAL ;
    PORT
      LAYER M4 ;
        RECT  0 115.248 0.084 115.272 ;
    END
  END src[336]
  PIN src[337]
    DIRECTION INPUT ;
    USE SIGNAL ;
    PORT
      LAYER M4 ;
        RECT  0 115.584 0.084 115.608 ;
    END
  END src[337]
  PIN src[338]
    DIRECTION INPUT ;
    USE SIGNAL ;
    PORT
      LAYER M4 ;
        RECT  0 115.872 0.084 115.896 ;
    END
  END src[338]
  PIN src[339]
    DIRECTION INPUT ;
    USE SIGNAL ;
    PORT
      LAYER M4 ;
        RECT  0 116.208 0.084 116.232 ;
    END
  END src[339]
  PIN src[33]
    DIRECTION INPUT ;
    USE SIGNAL ;
    PORT
      LAYER M6 ;
        RECT  0 20.736 0.07 20.768 ;
    END
  END src[33]
  PIN src[340]
    DIRECTION INPUT ;
    USE SIGNAL ;
    PORT
      LAYER M4 ;
        RECT  0 116.496 0.084 116.52 ;
    END
  END src[340]
  PIN src[341]
    DIRECTION INPUT ;
    USE SIGNAL ;
    PORT
      LAYER M4 ;
        RECT  0 116.832 0.084 116.856 ;
    END
  END src[341]
  PIN src[342]
    DIRECTION INPUT ;
    USE SIGNAL ;
    PORT
      LAYER M4 ;
        RECT  0 117.12 0.084 117.144 ;
    END
  END src[342]
  PIN src[343]
    DIRECTION INPUT ;
    USE SIGNAL ;
    PORT
      LAYER M4 ;
        RECT  0 117.456 0.084 117.48 ;
    END
  END src[343]
  PIN src[344]
    DIRECTION INPUT ;
    USE SIGNAL ;
    PORT
      LAYER M4 ;
        RECT  0 117.744 0.084 117.768 ;
    END
  END src[344]
  PIN src[345]
    DIRECTION INPUT ;
    USE SIGNAL ;
    PORT
      LAYER M4 ;
        RECT  0 118.08 0.084 118.104 ;
    END
  END src[345]
  PIN src[346]
    DIRECTION INPUT ;
    USE SIGNAL ;
    PORT
      LAYER M4 ;
        RECT  0 118.368 0.084 118.392 ;
    END
  END src[346]
  PIN src[347]
    DIRECTION INPUT ;
    USE SIGNAL ;
    PORT
      LAYER M4 ;
        RECT  0 118.704 0.084 118.728 ;
    END
  END src[347]
  PIN src[348]
    DIRECTION INPUT ;
    USE SIGNAL ;
    PORT
      LAYER M4 ;
        RECT  0 118.992 0.084 119.016 ;
    END
  END src[348]
  PIN src[349]
    DIRECTION INPUT ;
    USE SIGNAL ;
    PORT
      LAYER M4 ;
        RECT  0 119.328 0.084 119.352 ;
    END
  END src[349]
  PIN src[34]
    DIRECTION INPUT ;
    USE SIGNAL ;
    PORT
      LAYER M6 ;
        RECT  0 21.056 0.07 21.088 ;
    END
  END src[34]
  PIN src[350]
    DIRECTION INPUT ;
    USE SIGNAL ;
    PORT
      LAYER M4 ;
        RECT  0 119.616 0.084 119.64 ;
    END
  END src[350]
  PIN src[351]
    DIRECTION INPUT ;
    USE SIGNAL ;
    PORT
      LAYER M6 ;
        RECT  0 119.936 0.07 119.968 ;
    END
  END src[351]
  PIN src[352]
    DIRECTION INPUT ;
    USE SIGNAL ;
    PORT
      LAYER M6 ;
        RECT  0 120.256 0.07 120.288 ;
    END
  END src[352]
  PIN src[353]
    DIRECTION INPUT ;
    USE SIGNAL ;
    PORT
      LAYER M6 ;
        RECT  0 120.576 0.07 120.608 ;
    END
  END src[353]
  PIN src[354]
    DIRECTION INPUT ;
    USE SIGNAL ;
    PORT
      LAYER M6 ;
        RECT  0 120.832 0.07 120.864 ;
    END
  END src[354]
  PIN src[355]
    DIRECTION INPUT ;
    USE SIGNAL ;
    PORT
      LAYER M6 ;
        RECT  0 121.152 0.07 121.184 ;
    END
  END src[355]
  PIN src[356]
    DIRECTION INPUT ;
    USE SIGNAL ;
    PORT
      LAYER M6 ;
        RECT  0 121.472 0.07 121.504 ;
    END
  END src[356]
  PIN src[357]
    DIRECTION INPUT ;
    USE SIGNAL ;
    PORT
      LAYER M6 ;
        RECT  0 121.792 0.07 121.824 ;
    END
  END src[357]
  PIN src[358]
    DIRECTION INPUT ;
    USE SIGNAL ;
    PORT
      LAYER M6 ;
        RECT  0 122.112 0.07 122.144 ;
    END
  END src[358]
  PIN src[359]
    DIRECTION INPUT ;
    USE SIGNAL ;
    PORT
      LAYER M6 ;
        RECT  0 122.432 0.07 122.464 ;
    END
  END src[359]
  PIN src[35]
    DIRECTION INPUT ;
    USE SIGNAL ;
    PORT
      LAYER M6 ;
        RECT  0 21.376 0.07 21.408 ;
    END
  END src[35]
  PIN src[360]
    DIRECTION INPUT ;
    USE SIGNAL ;
    PORT
      LAYER M6 ;
        RECT  0 122.752 0.07 122.784 ;
    END
  END src[360]
  PIN src[361]
    DIRECTION INPUT ;
    USE SIGNAL ;
    PORT
      LAYER M6 ;
        RECT  0 123.072 0.07 123.104 ;
    END
  END src[361]
  PIN src[362]
    DIRECTION INPUT ;
    USE SIGNAL ;
    PORT
      LAYER M6 ;
        RECT  0 123.328 0.07 123.36 ;
    END
  END src[362]
  PIN src[363]
    DIRECTION INPUT ;
    USE SIGNAL ;
    PORT
      LAYER M6 ;
        RECT  0 123.648 0.07 123.68 ;
    END
  END src[363]
  PIN src[364]
    DIRECTION INPUT ;
    USE SIGNAL ;
    PORT
      LAYER M6 ;
        RECT  0 123.968 0.07 124 ;
    END
  END src[364]
  PIN src[365]
    DIRECTION INPUT ;
    USE SIGNAL ;
    PORT
      LAYER M6 ;
        RECT  0 124.288 0.07 124.32 ;
    END
  END src[365]
  PIN src[366]
    DIRECTION INPUT ;
    USE SIGNAL ;
    PORT
      LAYER M6 ;
        RECT  0 124.608 0.07 124.64 ;
    END
  END src[366]
  PIN src[367]
    DIRECTION INPUT ;
    USE SIGNAL ;
    PORT
      LAYER M6 ;
        RECT  0 124.928 0.07 124.96 ;
    END
  END src[367]
  PIN src[368]
    DIRECTION INPUT ;
    USE SIGNAL ;
    PORT
      LAYER M6 ;
        RECT  0 125.248 0.07 125.28 ;
    END
  END src[368]
  PIN src[369]
    DIRECTION INPUT ;
    USE SIGNAL ;
    PORT
      LAYER M6 ;
        RECT  0 125.568 0.07 125.6 ;
    END
  END src[369]
  PIN src[36]
    DIRECTION INPUT ;
    USE SIGNAL ;
    PORT
      LAYER M6 ;
        RECT  0 21.696 0.07 21.728 ;
    END
  END src[36]
  PIN src[370]
    DIRECTION INPUT ;
    USE SIGNAL ;
    PORT
      LAYER M6 ;
        RECT  0 125.824 0.07 125.856 ;
    END
  END src[370]
  PIN src[371]
    DIRECTION INPUT ;
    USE SIGNAL ;
    PORT
      LAYER M6 ;
        RECT  0 126.144 0.07 126.176 ;
    END
  END src[371]
  PIN src[372]
    DIRECTION INPUT ;
    USE SIGNAL ;
    PORT
      LAYER M6 ;
        RECT  0 126.464 0.07 126.496 ;
    END
  END src[372]
  PIN src[373]
    DIRECTION INPUT ;
    USE SIGNAL ;
    PORT
      LAYER M6 ;
        RECT  0 126.784 0.07 126.816 ;
    END
  END src[373]
  PIN src[374]
    DIRECTION INPUT ;
    USE SIGNAL ;
    PORT
      LAYER M6 ;
        RECT  0 127.104 0.07 127.136 ;
    END
  END src[374]
  PIN src[375]
    DIRECTION INPUT ;
    USE SIGNAL ;
    PORT
      LAYER M6 ;
        RECT  0 127.424 0.07 127.456 ;
    END
  END src[375]
  PIN src[376]
    DIRECTION INPUT ;
    USE SIGNAL ;
    PORT
      LAYER M6 ;
        RECT  0 127.744 0.07 127.776 ;
    END
  END src[376]
  PIN src[377]
    DIRECTION INPUT ;
    USE SIGNAL ;
    PORT
      LAYER M6 ;
        RECT  0 128.064 0.07 128.096 ;
    END
  END src[377]
  PIN src[378]
    DIRECTION INPUT ;
    USE SIGNAL ;
    PORT
      LAYER M6 ;
        RECT  0 128.32 0.07 128.352 ;
    END
  END src[378]
  PIN src[379]
    DIRECTION INPUT ;
    USE SIGNAL ;
    PORT
      LAYER M6 ;
        RECT  0 128.64 0.07 128.672 ;
    END
  END src[379]
  PIN src[37]
    DIRECTION INPUT ;
    USE SIGNAL ;
    PORT
      LAYER M6 ;
        RECT  0 22.016 0.07 22.048 ;
    END
  END src[37]
  PIN src[380]
    DIRECTION INPUT ;
    USE SIGNAL ;
    PORT
      LAYER M6 ;
        RECT  0 128.96 0.07 128.992 ;
    END
  END src[380]
  PIN src[381]
    DIRECTION INPUT ;
    USE SIGNAL ;
    PORT
      LAYER M6 ;
        RECT  0 129.28 0.07 129.312 ;
    END
  END src[381]
  PIN src[382]
    DIRECTION INPUT ;
    USE SIGNAL ;
    PORT
      LAYER M6 ;
        RECT  0 129.6 0.07 129.632 ;
    END
  END src[382]
  PIN src[383]
    DIRECTION INPUT ;
    USE SIGNAL ;
    PORT
      LAYER M4 ;
        RECT  0 129.888 0.084 129.912 ;
    END
  END src[383]
  PIN src[384]
    DIRECTION INPUT ;
    USE SIGNAL ;
    PORT
      LAYER M4 ;
        RECT  0 130.224 0.084 130.248 ;
    END
  END src[384]
  PIN src[385]
    DIRECTION INPUT ;
    USE SIGNAL ;
    PORT
      LAYER M4 ;
        RECT  0 130.512 0.084 130.536 ;
    END
  END src[385]
  PIN src[386]
    DIRECTION INPUT ;
    USE SIGNAL ;
    PORT
      LAYER M4 ;
        RECT  0 130.848 0.084 130.872 ;
    END
  END src[386]
  PIN src[387]
    DIRECTION INPUT ;
    USE SIGNAL ;
    PORT
      LAYER M4 ;
        RECT  0 131.136 0.084 131.16 ;
    END
  END src[387]
  PIN src[388]
    DIRECTION INPUT ;
    USE SIGNAL ;
    PORT
      LAYER M4 ;
        RECT  0 131.472 0.084 131.496 ;
    END
  END src[388]
  PIN src[389]
    DIRECTION INPUT ;
    USE SIGNAL ;
    PORT
      LAYER M4 ;
        RECT  0 131.76 0.084 131.784 ;
    END
  END src[389]
  PIN src[38]
    DIRECTION INPUT ;
    USE SIGNAL ;
    PORT
      LAYER M6 ;
        RECT  0 22.336 0.07 22.368 ;
    END
  END src[38]
  PIN src[390]
    DIRECTION INPUT ;
    USE SIGNAL ;
    PORT
      LAYER M4 ;
        RECT  0 132.096 0.084 132.12 ;
    END
  END src[390]
  PIN src[391]
    DIRECTION INPUT ;
    USE SIGNAL ;
    PORT
      LAYER M4 ;
        RECT  0 132.384 0.084 132.408 ;
    END
  END src[391]
  PIN src[392]
    DIRECTION INPUT ;
    USE SIGNAL ;
    PORT
      LAYER M4 ;
        RECT  0 132.72 0.084 132.744 ;
    END
  END src[392]
  PIN src[393]
    DIRECTION INPUT ;
    USE SIGNAL ;
    PORT
      LAYER M4 ;
        RECT  0 133.008 0.084 133.032 ;
    END
  END src[393]
  PIN src[394]
    DIRECTION INPUT ;
    USE SIGNAL ;
    PORT
      LAYER M4 ;
        RECT  0 133.344 0.084 133.368 ;
    END
  END src[394]
  PIN src[395]
    DIRECTION INPUT ;
    USE SIGNAL ;
    PORT
      LAYER M4 ;
        RECT  0 133.632 0.084 133.656 ;
    END
  END src[395]
  PIN src[396]
    DIRECTION INPUT ;
    USE SIGNAL ;
    PORT
      LAYER M4 ;
        RECT  0 133.968 0.084 133.992 ;
    END
  END src[396]
  PIN src[397]
    DIRECTION INPUT ;
    USE SIGNAL ;
    PORT
      LAYER M4 ;
        RECT  0 134.256 0.084 134.28 ;
    END
  END src[397]
  PIN src[398]
    DIRECTION INPUT ;
    USE SIGNAL ;
    PORT
      LAYER M4 ;
        RECT  0 134.592 0.084 134.616 ;
    END
  END src[398]
  PIN src[399]
    DIRECTION INPUT ;
    USE SIGNAL ;
    PORT
      LAYER M4 ;
        RECT  0 134.88 0.084 134.904 ;
    END
  END src[399]
  PIN src[39]
    DIRECTION INPUT ;
    USE SIGNAL ;
    PORT
      LAYER M6 ;
        RECT  0 22.592 0.07 22.624 ;
    END
  END src[39]
  PIN src[3]
    DIRECTION INPUT ;
    USE SIGNAL ;
    PORT
      LAYER M4 ;
        RECT  0 11.376 0.084 11.4 ;
    END
  END src[3]
  PIN src[400]
    DIRECTION INPUT ;
    USE SIGNAL ;
    PORT
      LAYER M4 ;
        RECT  0 135.216 0.084 135.24 ;
    END
  END src[400]
  PIN src[401]
    DIRECTION INPUT ;
    USE SIGNAL ;
    PORT
      LAYER M4 ;
        RECT  0 135.504 0.084 135.528 ;
    END
  END src[401]
  PIN src[402]
    DIRECTION INPUT ;
    USE SIGNAL ;
    PORT
      LAYER M4 ;
        RECT  0 135.84 0.084 135.864 ;
    END
  END src[402]
  PIN src[403]
    DIRECTION INPUT ;
    USE SIGNAL ;
    PORT
      LAYER M4 ;
        RECT  0 136.128 0.084 136.152 ;
    END
  END src[403]
  PIN src[404]
    DIRECTION INPUT ;
    USE SIGNAL ;
    PORT
      LAYER M4 ;
        RECT  0 136.464 0.084 136.488 ;
    END
  END src[404]
  PIN src[405]
    DIRECTION INPUT ;
    USE SIGNAL ;
    PORT
      LAYER M4 ;
        RECT  0 136.752 0.084 136.776 ;
    END
  END src[405]
  PIN src[406]
    DIRECTION INPUT ;
    USE SIGNAL ;
    PORT
      LAYER M4 ;
        RECT  0 137.088 0.084 137.112 ;
    END
  END src[406]
  PIN src[407]
    DIRECTION INPUT ;
    USE SIGNAL ;
    PORT
      LAYER M4 ;
        RECT  0 137.376 0.084 137.4 ;
    END
  END src[407]
  PIN src[408]
    DIRECTION INPUT ;
    USE SIGNAL ;
    PORT
      LAYER M4 ;
        RECT  0 137.712 0.084 137.736 ;
    END
  END src[408]
  PIN src[409]
    DIRECTION INPUT ;
    USE SIGNAL ;
    PORT
      LAYER M4 ;
        RECT  0 138 0.084 138.024 ;
    END
  END src[409]
  PIN src[40]
    DIRECTION INPUT ;
    USE SIGNAL ;
    PORT
      LAYER M6 ;
        RECT  0 22.912 0.07 22.944 ;
    END
  END src[40]
  PIN src[410]
    DIRECTION INPUT ;
    USE SIGNAL ;
    PORT
      LAYER M4 ;
        RECT  0 138.336 0.084 138.36 ;
    END
  END src[410]
  PIN src[411]
    DIRECTION INPUT ;
    USE SIGNAL ;
    PORT
      LAYER M4 ;
        RECT  0 138.624 0.084 138.648 ;
    END
  END src[411]
  PIN src[412]
    DIRECTION INPUT ;
    USE SIGNAL ;
    PORT
      LAYER M4 ;
        RECT  0 138.96 0.084 138.984 ;
    END
  END src[412]
  PIN src[413]
    DIRECTION INPUT ;
    USE SIGNAL ;
    PORT
      LAYER M4 ;
        RECT  0 139.248 0.084 139.272 ;
    END
  END src[413]
  PIN src[414]
    DIRECTION INPUT ;
    USE SIGNAL ;
    PORT
      LAYER M4 ;
        RECT  0 139.584 0.084 139.608 ;
    END
  END src[414]
  PIN src[415]
    DIRECTION INPUT ;
    USE SIGNAL ;
    PORT
      LAYER M6 ;
        RECT  0 139.904 0.07 139.936 ;
    END
  END src[415]
  PIN src[416]
    DIRECTION INPUT ;
    USE SIGNAL ;
    PORT
      LAYER M6 ;
        RECT  0 140.224 0.07 140.256 ;
    END
  END src[416]
  PIN src[417]
    DIRECTION INPUT ;
    USE SIGNAL ;
    PORT
      LAYER M6 ;
        RECT  0 140.48 0.07 140.512 ;
    END
  END src[417]
  PIN src[418]
    DIRECTION INPUT ;
    USE SIGNAL ;
    PORT
      LAYER M6 ;
        RECT  0 140.8 0.07 140.832 ;
    END
  END src[418]
  PIN src[419]
    DIRECTION INPUT ;
    USE SIGNAL ;
    PORT
      LAYER M6 ;
        RECT  0 141.12 0.07 141.152 ;
    END
  END src[419]
  PIN src[41]
    DIRECTION INPUT ;
    USE SIGNAL ;
    PORT
      LAYER M6 ;
        RECT  0 23.232 0.07 23.264 ;
    END
  END src[41]
  PIN src[420]
    DIRECTION INPUT ;
    USE SIGNAL ;
    PORT
      LAYER M6 ;
        RECT  0 141.44 0.07 141.472 ;
    END
  END src[420]
  PIN src[421]
    DIRECTION INPUT ;
    USE SIGNAL ;
    PORT
      LAYER M6 ;
        RECT  0 141.76 0.07 141.792 ;
    END
  END src[421]
  PIN src[422]
    DIRECTION INPUT ;
    USE SIGNAL ;
    PORT
      LAYER M6 ;
        RECT  0 142.08 0.07 142.112 ;
    END
  END src[422]
  PIN src[423]
    DIRECTION INPUT ;
    USE SIGNAL ;
    PORT
      LAYER M6 ;
        RECT  0 142.4 0.07 142.432 ;
    END
  END src[423]
  PIN src[424]
    DIRECTION INPUT ;
    USE SIGNAL ;
    PORT
      LAYER M6 ;
        RECT  0 142.72 0.07 142.752 ;
    END
  END src[424]
  PIN src[425]
    DIRECTION INPUT ;
    USE SIGNAL ;
    PORT
      LAYER M6 ;
        RECT  0 142.976 0.07 143.008 ;
    END
  END src[425]
  PIN src[426]
    DIRECTION INPUT ;
    USE SIGNAL ;
    PORT
      LAYER M6 ;
        RECT  0 143.296 0.07 143.328 ;
    END
  END src[426]
  PIN src[427]
    DIRECTION INPUT ;
    USE SIGNAL ;
    PORT
      LAYER M6 ;
        RECT  0 143.616 0.07 143.648 ;
    END
  END src[427]
  PIN src[428]
    DIRECTION INPUT ;
    USE SIGNAL ;
    PORT
      LAYER M6 ;
        RECT  0 143.936 0.07 143.968 ;
    END
  END src[428]
  PIN src[429]
    DIRECTION INPUT ;
    USE SIGNAL ;
    PORT
      LAYER M6 ;
        RECT  0 144.256 0.07 144.288 ;
    END
  END src[429]
  PIN src[42]
    DIRECTION INPUT ;
    USE SIGNAL ;
    PORT
      LAYER M6 ;
        RECT  0 23.552 0.07 23.584 ;
    END
  END src[42]
  PIN src[430]
    DIRECTION INPUT ;
    USE SIGNAL ;
    PORT
      LAYER M6 ;
        RECT  0 144.576 0.07 144.608 ;
    END
  END src[430]
  PIN src[431]
    DIRECTION INPUT ;
    USE SIGNAL ;
    PORT
      LAYER M6 ;
        RECT  0 144.896 0.07 144.928 ;
    END
  END src[431]
  PIN src[432]
    DIRECTION INPUT ;
    USE SIGNAL ;
    PORT
      LAYER M6 ;
        RECT  0 145.216 0.07 145.248 ;
    END
  END src[432]
  PIN src[433]
    DIRECTION INPUT ;
    USE SIGNAL ;
    PORT
      LAYER M6 ;
        RECT  0 145.472 0.07 145.504 ;
    END
  END src[433]
  PIN src[434]
    DIRECTION INPUT ;
    USE SIGNAL ;
    PORT
      LAYER M6 ;
        RECT  0 145.792 0.07 145.824 ;
    END
  END src[434]
  PIN src[435]
    DIRECTION INPUT ;
    USE SIGNAL ;
    PORT
      LAYER M6 ;
        RECT  0 146.112 0.07 146.144 ;
    END
  END src[435]
  PIN src[436]
    DIRECTION INPUT ;
    USE SIGNAL ;
    PORT
      LAYER M6 ;
        RECT  0 146.432 0.07 146.464 ;
    END
  END src[436]
  PIN src[437]
    DIRECTION INPUT ;
    USE SIGNAL ;
    PORT
      LAYER M6 ;
        RECT  0 146.752 0.07 146.784 ;
    END
  END src[437]
  PIN src[438]
    DIRECTION INPUT ;
    USE SIGNAL ;
    PORT
      LAYER M6 ;
        RECT  0 147.072 0.07 147.104 ;
    END
  END src[438]
  PIN src[439]
    DIRECTION INPUT ;
    USE SIGNAL ;
    PORT
      LAYER M6 ;
        RECT  0 147.392 0.07 147.424 ;
    END
  END src[439]
  PIN src[43]
    DIRECTION INPUT ;
    USE SIGNAL ;
    PORT
      LAYER M6 ;
        RECT  0 23.872 0.07 23.904 ;
    END
  END src[43]
  PIN src[440]
    DIRECTION INPUT ;
    USE SIGNAL ;
    PORT
      LAYER M6 ;
        RECT  0 147.712 0.07 147.744 ;
    END
  END src[440]
  PIN src[441]
    DIRECTION INPUT ;
    USE SIGNAL ;
    PORT
      LAYER M6 ;
        RECT  0 147.968 0.07 148 ;
    END
  END src[441]
  PIN src[442]
    DIRECTION INPUT ;
    USE SIGNAL ;
    PORT
      LAYER M6 ;
        RECT  0 148.288 0.07 148.32 ;
    END
  END src[442]
  PIN src[443]
    DIRECTION INPUT ;
    USE SIGNAL ;
    PORT
      LAYER M6 ;
        RECT  0 148.608 0.07 148.64 ;
    END
  END src[443]
  PIN src[444]
    DIRECTION INPUT ;
    USE SIGNAL ;
    PORT
      LAYER M6 ;
        RECT  0 148.928 0.07 148.96 ;
    END
  END src[444]
  PIN src[445]
    DIRECTION INPUT ;
    USE SIGNAL ;
    PORT
      LAYER M6 ;
        RECT  0 149.248 0.07 149.28 ;
    END
  END src[445]
  PIN src[446]
    DIRECTION INPUT ;
    USE SIGNAL ;
    PORT
      LAYER M6 ;
        RECT  0 149.568 0.07 149.6 ;
    END
  END src[446]
  PIN src[447]
    DIRECTION INPUT ;
    USE SIGNAL ;
    PORT
      LAYER M4 ;
        RECT  0 149.856 0.084 149.88 ;
    END
  END src[447]
  PIN src[448]
    DIRECTION INPUT ;
    USE SIGNAL ;
    PORT
      LAYER M4 ;
        RECT  0 150.192 0.084 150.216 ;
    END
  END src[448]
  PIN src[449]
    DIRECTION INPUT ;
    USE SIGNAL ;
    PORT
      LAYER M4 ;
        RECT  0 150.48 0.084 150.504 ;
    END
  END src[449]
  PIN src[44]
    DIRECTION INPUT ;
    USE SIGNAL ;
    PORT
      LAYER M6 ;
        RECT  0 24.192 0.07 24.224 ;
    END
  END src[44]
  PIN src[450]
    DIRECTION INPUT ;
    USE SIGNAL ;
    PORT
      LAYER M4 ;
        RECT  0 150.816 0.084 150.84 ;
    END
  END src[450]
  PIN src[451]
    DIRECTION INPUT ;
    USE SIGNAL ;
    PORT
      LAYER M4 ;
        RECT  0 151.104 0.084 151.128 ;
    END
  END src[451]
  PIN src[452]
    DIRECTION INPUT ;
    USE SIGNAL ;
    PORT
      LAYER M4 ;
        RECT  0 151.44 0.084 151.464 ;
    END
  END src[452]
  PIN src[453]
    DIRECTION INPUT ;
    USE SIGNAL ;
    PORT
      LAYER M4 ;
        RECT  0 151.728 0.084 151.752 ;
    END
  END src[453]
  PIN src[454]
    DIRECTION INPUT ;
    USE SIGNAL ;
    PORT
      LAYER M4 ;
        RECT  0 152.064 0.084 152.088 ;
    END
  END src[454]
  PIN src[455]
    DIRECTION INPUT ;
    USE SIGNAL ;
    PORT
      LAYER M4 ;
        RECT  0 152.352 0.084 152.376 ;
    END
  END src[455]
  PIN src[456]
    DIRECTION INPUT ;
    USE SIGNAL ;
    PORT
      LAYER M4 ;
        RECT  0 152.688 0.084 152.712 ;
    END
  END src[456]
  PIN src[457]
    DIRECTION INPUT ;
    USE SIGNAL ;
    PORT
      LAYER M4 ;
        RECT  0 152.976 0.084 153 ;
    END
  END src[457]
  PIN src[458]
    DIRECTION INPUT ;
    USE SIGNAL ;
    PORT
      LAYER M4 ;
        RECT  0 153.312 0.084 153.336 ;
    END
  END src[458]
  PIN src[459]
    DIRECTION INPUT ;
    USE SIGNAL ;
    PORT
      LAYER M4 ;
        RECT  0 153.6 0.084 153.624 ;
    END
  END src[459]
  PIN src[45]
    DIRECTION INPUT ;
    USE SIGNAL ;
    PORT
      LAYER M6 ;
        RECT  0 24.512 0.07 24.544 ;
    END
  END src[45]
  PIN src[460]
    DIRECTION INPUT ;
    USE SIGNAL ;
    PORT
      LAYER M4 ;
        RECT  0 153.936 0.084 153.96 ;
    END
  END src[460]
  PIN src[461]
    DIRECTION INPUT ;
    USE SIGNAL ;
    PORT
      LAYER M4 ;
        RECT  0 154.224 0.084 154.248 ;
    END
  END src[461]
  PIN src[462]
    DIRECTION INPUT ;
    USE SIGNAL ;
    PORT
      LAYER M4 ;
        RECT  0 154.56 0.084 154.584 ;
    END
  END src[462]
  PIN src[463]
    DIRECTION INPUT ;
    USE SIGNAL ;
    PORT
      LAYER M4 ;
        RECT  0 154.848 0.084 154.872 ;
    END
  END src[463]
  PIN src[464]
    DIRECTION INPUT ;
    USE SIGNAL ;
    PORT
      LAYER M4 ;
        RECT  0 155.184 0.084 155.208 ;
    END
  END src[464]
  PIN src[465]
    DIRECTION INPUT ;
    USE SIGNAL ;
    PORT
      LAYER M4 ;
        RECT  0 155.472 0.084 155.496 ;
    END
  END src[465]
  PIN src[466]
    DIRECTION INPUT ;
    USE SIGNAL ;
    PORT
      LAYER M4 ;
        RECT  0 155.808 0.084 155.832 ;
    END
  END src[466]
  PIN src[467]
    DIRECTION INPUT ;
    USE SIGNAL ;
    PORT
      LAYER M4 ;
        RECT  0 156.096 0.084 156.12 ;
    END
  END src[467]
  PIN src[468]
    DIRECTION INPUT ;
    USE SIGNAL ;
    PORT
      LAYER M4 ;
        RECT  0 156.432 0.084 156.456 ;
    END
  END src[468]
  PIN src[469]
    DIRECTION INPUT ;
    USE SIGNAL ;
    PORT
      LAYER M4 ;
        RECT  0 156.72 0.084 156.744 ;
    END
  END src[469]
  PIN src[46]
    DIRECTION INPUT ;
    USE SIGNAL ;
    PORT
      LAYER M6 ;
        RECT  0 24.768 0.07 24.8 ;
    END
  END src[46]
  PIN src[470]
    DIRECTION INPUT ;
    USE SIGNAL ;
    PORT
      LAYER M4 ;
        RECT  0 157.056 0.084 157.08 ;
    END
  END src[470]
  PIN src[471]
    DIRECTION INPUT ;
    USE SIGNAL ;
    PORT
      LAYER M4 ;
        RECT  0 157.344 0.084 157.368 ;
    END
  END src[471]
  PIN src[472]
    DIRECTION INPUT ;
    USE SIGNAL ;
    PORT
      LAYER M4 ;
        RECT  0 157.68 0.084 157.704 ;
    END
  END src[472]
  PIN src[473]
    DIRECTION INPUT ;
    USE SIGNAL ;
    PORT
      LAYER M4 ;
        RECT  0 157.968 0.084 157.992 ;
    END
  END src[473]
  PIN src[474]
    DIRECTION INPUT ;
    USE SIGNAL ;
    PORT
      LAYER M4 ;
        RECT  0 158.304 0.084 158.328 ;
    END
  END src[474]
  PIN src[475]
    DIRECTION INPUT ;
    USE SIGNAL ;
    PORT
      LAYER M4 ;
        RECT  0 158.592 0.084 158.616 ;
    END
  END src[475]
  PIN src[476]
    DIRECTION INPUT ;
    USE SIGNAL ;
    PORT
      LAYER M4 ;
        RECT  0 158.928 0.084 158.952 ;
    END
  END src[476]
  PIN src[477]
    DIRECTION INPUT ;
    USE SIGNAL ;
    PORT
      LAYER M4 ;
        RECT  0 159.216 0.084 159.24 ;
    END
  END src[477]
  PIN src[478]
    DIRECTION INPUT ;
    USE SIGNAL ;
    PORT
      LAYER M4 ;
        RECT  0 159.552 0.084 159.576 ;
    END
  END src[478]
  PIN src[479]
    DIRECTION INPUT ;
    USE SIGNAL ;
    PORT
      LAYER M6 ;
        RECT  0 159.872 0.07 159.904 ;
    END
  END src[479]
  PIN src[47]
    DIRECTION INPUT ;
    USE SIGNAL ;
    PORT
      LAYER M6 ;
        RECT  0 25.088 0.07 25.12 ;
    END
  END src[47]
  PIN src[480]
    DIRECTION INPUT ;
    USE SIGNAL ;
    PORT
      LAYER M6 ;
        RECT  0 160.128 0.07 160.16 ;
    END
  END src[480]
  PIN src[481]
    DIRECTION INPUT ;
    USE SIGNAL ;
    PORT
      LAYER M6 ;
        RECT  0 160.448 0.07 160.48 ;
    END
  END src[481]
  PIN src[482]
    DIRECTION INPUT ;
    USE SIGNAL ;
    PORT
      LAYER M6 ;
        RECT  0 160.768 0.07 160.8 ;
    END
  END src[482]
  PIN src[483]
    DIRECTION INPUT ;
    USE SIGNAL ;
    PORT
      LAYER M6 ;
        RECT  0 161.088 0.07 161.12 ;
    END
  END src[483]
  PIN src[484]
    DIRECTION INPUT ;
    USE SIGNAL ;
    PORT
      LAYER M6 ;
        RECT  0 161.408 0.07 161.44 ;
    END
  END src[484]
  PIN src[485]
    DIRECTION INPUT ;
    USE SIGNAL ;
    PORT
      LAYER M6 ;
        RECT  0 161.728 0.07 161.76 ;
    END
  END src[485]
  PIN src[486]
    DIRECTION INPUT ;
    USE SIGNAL ;
    PORT
      LAYER M6 ;
        RECT  0 162.048 0.07 162.08 ;
    END
  END src[486]
  PIN src[487]
    DIRECTION INPUT ;
    USE SIGNAL ;
    PORT
      LAYER M6 ;
        RECT  0 162.368 0.07 162.4 ;
    END
  END src[487]
  PIN src[488]
    DIRECTION INPUT ;
    USE SIGNAL ;
    PORT
      LAYER M6 ;
        RECT  0 162.624 0.07 162.656 ;
    END
  END src[488]
  PIN src[489]
    DIRECTION INPUT ;
    USE SIGNAL ;
    PORT
      LAYER M6 ;
        RECT  0 162.944 0.07 162.976 ;
    END
  END src[489]
  PIN src[48]
    DIRECTION INPUT ;
    USE SIGNAL ;
    PORT
      LAYER M6 ;
        RECT  0 25.408 0.07 25.44 ;
    END
  END src[48]
  PIN src[490]
    DIRECTION INPUT ;
    USE SIGNAL ;
    PORT
      LAYER M6 ;
        RECT  0 163.264 0.07 163.296 ;
    END
  END src[490]
  PIN src[491]
    DIRECTION INPUT ;
    USE SIGNAL ;
    PORT
      LAYER M6 ;
        RECT  0 163.584 0.07 163.616 ;
    END
  END src[491]
  PIN src[492]
    DIRECTION INPUT ;
    USE SIGNAL ;
    PORT
      LAYER M6 ;
        RECT  0 163.904 0.07 163.936 ;
    END
  END src[492]
  PIN src[493]
    DIRECTION INPUT ;
    USE SIGNAL ;
    PORT
      LAYER M6 ;
        RECT  0 164.224 0.07 164.256 ;
    END
  END src[493]
  PIN src[494]
    DIRECTION INPUT ;
    USE SIGNAL ;
    PORT
      LAYER M6 ;
        RECT  0 164.544 0.07 164.576 ;
    END
  END src[494]
  PIN src[495]
    DIRECTION INPUT ;
    USE SIGNAL ;
    PORT
      LAYER M6 ;
        RECT  0 164.864 0.07 164.896 ;
    END
  END src[495]
  PIN src[496]
    DIRECTION INPUT ;
    USE SIGNAL ;
    PORT
      LAYER M6 ;
        RECT  0 165.12 0.07 165.152 ;
    END
  END src[496]
  PIN src[497]
    DIRECTION INPUT ;
    USE SIGNAL ;
    PORT
      LAYER M6 ;
        RECT  0 165.44 0.07 165.472 ;
    END
  END src[497]
  PIN src[498]
    DIRECTION INPUT ;
    USE SIGNAL ;
    PORT
      LAYER M6 ;
        RECT  0 165.76 0.07 165.792 ;
    END
  END src[498]
  PIN src[499]
    DIRECTION INPUT ;
    USE SIGNAL ;
    PORT
      LAYER M6 ;
        RECT  0 166.08 0.07 166.112 ;
    END
  END src[499]
  PIN src[49]
    DIRECTION INPUT ;
    USE SIGNAL ;
    PORT
      LAYER M6 ;
        RECT  0 25.728 0.07 25.76 ;
    END
  END src[49]
  PIN src[4]
    DIRECTION INPUT ;
    USE SIGNAL ;
    PORT
      LAYER M4 ;
        RECT  0 11.712 0.084 11.736 ;
    END
  END src[4]
  PIN src[500]
    DIRECTION INPUT ;
    USE SIGNAL ;
    PORT
      LAYER M6 ;
        RECT  0 166.4 0.07 166.432 ;
    END
  END src[500]
  PIN src[501]
    DIRECTION INPUT ;
    USE SIGNAL ;
    PORT
      LAYER M6 ;
        RECT  0 166.72 0.07 166.752 ;
    END
  END src[501]
  PIN src[502]
    DIRECTION INPUT ;
    USE SIGNAL ;
    PORT
      LAYER M6 ;
        RECT  0 167.04 0.07 167.072 ;
    END
  END src[502]
  PIN src[503]
    DIRECTION INPUT ;
    USE SIGNAL ;
    PORT
      LAYER M6 ;
        RECT  0 167.36 0.07 167.392 ;
    END
  END src[503]
  PIN src[504]
    DIRECTION INPUT ;
    USE SIGNAL ;
    PORT
      LAYER M6 ;
        RECT  0 167.616 0.07 167.648 ;
    END
  END src[504]
  PIN src[505]
    DIRECTION INPUT ;
    USE SIGNAL ;
    PORT
      LAYER M6 ;
        RECT  0 167.936 0.07 167.968 ;
    END
  END src[505]
  PIN src[506]
    DIRECTION INPUT ;
    USE SIGNAL ;
    PORT
      LAYER M6 ;
        RECT  0 168.256 0.07 168.288 ;
    END
  END src[506]
  PIN src[507]
    DIRECTION INPUT ;
    USE SIGNAL ;
    PORT
      LAYER M6 ;
        RECT  0 168.576 0.07 168.608 ;
    END
  END src[507]
  PIN src[508]
    DIRECTION INPUT ;
    USE SIGNAL ;
    PORT
      LAYER M6 ;
        RECT  0 168.896 0.07 168.928 ;
    END
  END src[508]
  PIN src[509]
    DIRECTION INPUT ;
    USE SIGNAL ;
    PORT
      LAYER M6 ;
        RECT  0 169.216 0.07 169.248 ;
    END
  END src[509]
  PIN src[50]
    DIRECTION INPUT ;
    USE SIGNAL ;
    PORT
      LAYER M6 ;
        RECT  0 26.048 0.07 26.08 ;
    END
  END src[50]
  PIN src[510]
    DIRECTION INPUT ;
    USE SIGNAL ;
    PORT
      LAYER M6 ;
        RECT  0 169.536 0.07 169.568 ;
    END
  END src[510]
  PIN src[511]
    DIRECTION INPUT ;
    USE SIGNAL ;
    PORT
      LAYER M4 ;
        RECT  0 169.824 0.084 169.848 ;
    END
  END src[511]
  PIN src[51]
    DIRECTION INPUT ;
    USE SIGNAL ;
    PORT
      LAYER M6 ;
        RECT  0 26.368 0.07 26.4 ;
    END
  END src[51]
  PIN src[52]
    DIRECTION INPUT ;
    USE SIGNAL ;
    PORT
      LAYER M6 ;
        RECT  0 26.688 0.07 26.72 ;
    END
  END src[52]
  PIN src[53]
    DIRECTION INPUT ;
    USE SIGNAL ;
    PORT
      LAYER M6 ;
        RECT  0 27.008 0.07 27.04 ;
    END
  END src[53]
  PIN src[54]
    DIRECTION INPUT ;
    USE SIGNAL ;
    PORT
      LAYER M6 ;
        RECT  0 27.264 0.07 27.296 ;
    END
  END src[54]
  PIN src[55]
    DIRECTION INPUT ;
    USE SIGNAL ;
    PORT
      LAYER M6 ;
        RECT  0 27.584 0.07 27.616 ;
    END
  END src[55]
  PIN src[56]
    DIRECTION INPUT ;
    USE SIGNAL ;
    PORT
      LAYER M6 ;
        RECT  0 27.904 0.07 27.936 ;
    END
  END src[56]
  PIN src[57]
    DIRECTION INPUT ;
    USE SIGNAL ;
    PORT
      LAYER M6 ;
        RECT  0 28.224 0.07 28.256 ;
    END
  END src[57]
  PIN src[58]
    DIRECTION INPUT ;
    USE SIGNAL ;
    PORT
      LAYER M6 ;
        RECT  0 28.544 0.07 28.576 ;
    END
  END src[58]
  PIN src[59]
    DIRECTION INPUT ;
    USE SIGNAL ;
    PORT
      LAYER M6 ;
        RECT  0 28.864 0.07 28.896 ;
    END
  END src[59]
  PIN src[5]
    DIRECTION INPUT ;
    USE SIGNAL ;
    PORT
      LAYER M4 ;
        RECT  0 12 0.084 12.024 ;
    END
  END src[5]
  PIN src[60]
    DIRECTION INPUT ;
    USE SIGNAL ;
    PORT
      LAYER M6 ;
        RECT  0 29.184 0.07 29.216 ;
    END
  END src[60]
  PIN src[61]
    DIRECTION INPUT ;
    USE SIGNAL ;
    PORT
      LAYER M6 ;
        RECT  0 29.504 0.07 29.536 ;
    END
  END src[61]
  PIN src[62]
    DIRECTION INPUT ;
    USE SIGNAL ;
    PORT
      LAYER M6 ;
        RECT  0 29.76 0.07 29.792 ;
    END
  END src[62]
  PIN src[63]
    DIRECTION INPUT ;
    USE SIGNAL ;
    PORT
      LAYER M4 ;
        RECT  0 30.096 0.084 30.12 ;
    END
  END src[63]
  PIN src[64]
    DIRECTION INPUT ;
    USE SIGNAL ;
    PORT
      LAYER M4 ;
        RECT  0 30.432 0.084 30.456 ;
    END
  END src[64]
  PIN src[65]
    DIRECTION INPUT ;
    USE SIGNAL ;
    PORT
      LAYER M4 ;
        RECT  0 30.72 0.084 30.744 ;
    END
  END src[65]
  PIN src[66]
    DIRECTION INPUT ;
    USE SIGNAL ;
    PORT
      LAYER M4 ;
        RECT  0 31.056 0.084 31.08 ;
    END
  END src[66]
  PIN src[67]
    DIRECTION INPUT ;
    USE SIGNAL ;
    PORT
      LAYER M4 ;
        RECT  0 31.344 0.084 31.368 ;
    END
  END src[67]
  PIN src[68]
    DIRECTION INPUT ;
    USE SIGNAL ;
    PORT
      LAYER M4 ;
        RECT  0 31.68 0.084 31.704 ;
    END
  END src[68]
  PIN src[69]
    DIRECTION INPUT ;
    USE SIGNAL ;
    PORT
      LAYER M4 ;
        RECT  0 31.968 0.084 31.992 ;
    END
  END src[69]
  PIN src[6]
    DIRECTION INPUT ;
    USE SIGNAL ;
    PORT
      LAYER M4 ;
        RECT  0 12.336 0.084 12.36 ;
    END
  END src[6]
  PIN src[70]
    DIRECTION INPUT ;
    USE SIGNAL ;
    PORT
      LAYER M4 ;
        RECT  0 32.304 0.084 32.328 ;
    END
  END src[70]
  PIN src[71]
    DIRECTION INPUT ;
    USE SIGNAL ;
    PORT
      LAYER M4 ;
        RECT  0 32.592 0.084 32.616 ;
    END
  END src[71]
  PIN src[72]
    DIRECTION INPUT ;
    USE SIGNAL ;
    PORT
      LAYER M4 ;
        RECT  0 32.928 0.084 32.952 ;
    END
  END src[72]
  PIN src[73]
    DIRECTION INPUT ;
    USE SIGNAL ;
    PORT
      LAYER M4 ;
        RECT  0 33.216 0.084 33.24 ;
    END
  END src[73]
  PIN src[74]
    DIRECTION INPUT ;
    USE SIGNAL ;
    PORT
      LAYER M4 ;
        RECT  0 33.552 0.084 33.576 ;
    END
  END src[74]
  PIN src[75]
    DIRECTION INPUT ;
    USE SIGNAL ;
    PORT
      LAYER M4 ;
        RECT  0 33.84 0.084 33.864 ;
    END
  END src[75]
  PIN src[76]
    DIRECTION INPUT ;
    USE SIGNAL ;
    PORT
      LAYER M4 ;
        RECT  0 34.176 0.084 34.2 ;
    END
  END src[76]
  PIN src[77]
    DIRECTION INPUT ;
    USE SIGNAL ;
    PORT
      LAYER M4 ;
        RECT  0 34.464 0.084 34.488 ;
    END
  END src[77]
  PIN src[78]
    DIRECTION INPUT ;
    USE SIGNAL ;
    PORT
      LAYER M4 ;
        RECT  0 34.8 0.084 34.824 ;
    END
  END src[78]
  PIN src[79]
    DIRECTION INPUT ;
    USE SIGNAL ;
    PORT
      LAYER M4 ;
        RECT  0 35.088 0.084 35.112 ;
    END
  END src[79]
  PIN src[7]
    DIRECTION INPUT ;
    USE SIGNAL ;
    PORT
      LAYER M4 ;
        RECT  0 12.624 0.084 12.648 ;
    END
  END src[7]
  PIN src[80]
    DIRECTION INPUT ;
    USE SIGNAL ;
    PORT
      LAYER M4 ;
        RECT  0 35.424 0.084 35.448 ;
    END
  END src[80]
  PIN src[81]
    DIRECTION INPUT ;
    USE SIGNAL ;
    PORT
      LAYER M4 ;
        RECT  0 35.712 0.084 35.736 ;
    END
  END src[81]
  PIN src[82]
    DIRECTION INPUT ;
    USE SIGNAL ;
    PORT
      LAYER M4 ;
        RECT  0 36.048 0.084 36.072 ;
    END
  END src[82]
  PIN src[83]
    DIRECTION INPUT ;
    USE SIGNAL ;
    PORT
      LAYER M4 ;
        RECT  0 36.336 0.084 36.36 ;
    END
  END src[83]
  PIN src[84]
    DIRECTION INPUT ;
    USE SIGNAL ;
    PORT
      LAYER M4 ;
        RECT  0 36.672 0.084 36.696 ;
    END
  END src[84]
  PIN src[85]
    DIRECTION INPUT ;
    USE SIGNAL ;
    PORT
      LAYER M4 ;
        RECT  0 36.96 0.084 36.984 ;
    END
  END src[85]
  PIN src[86]
    DIRECTION INPUT ;
    USE SIGNAL ;
    PORT
      LAYER M4 ;
        RECT  0 37.296 0.084 37.32 ;
    END
  END src[86]
  PIN src[87]
    DIRECTION INPUT ;
    USE SIGNAL ;
    PORT
      LAYER M4 ;
        RECT  0 37.584 0.084 37.608 ;
    END
  END src[87]
  PIN src[88]
    DIRECTION INPUT ;
    USE SIGNAL ;
    PORT
      LAYER M4 ;
        RECT  0 37.92 0.084 37.944 ;
    END
  END src[88]
  PIN src[89]
    DIRECTION INPUT ;
    USE SIGNAL ;
    PORT
      LAYER M4 ;
        RECT  0 38.208 0.084 38.232 ;
    END
  END src[89]
  PIN src[8]
    DIRECTION INPUT ;
    USE SIGNAL ;
    PORT
      LAYER M4 ;
        RECT  0 12.96 0.084 12.984 ;
    END
  END src[8]
  PIN src[90]
    DIRECTION INPUT ;
    USE SIGNAL ;
    PORT
      LAYER M4 ;
        RECT  0 38.544 0.084 38.568 ;
    END
  END src[90]
  PIN src[91]
    DIRECTION INPUT ;
    USE SIGNAL ;
    PORT
      LAYER M4 ;
        RECT  0 38.832 0.084 38.856 ;
    END
  END src[91]
  PIN src[92]
    DIRECTION INPUT ;
    USE SIGNAL ;
    PORT
      LAYER M4 ;
        RECT  0 39.168 0.084 39.192 ;
    END
  END src[92]
  PIN src[93]
    DIRECTION INPUT ;
    USE SIGNAL ;
    PORT
      LAYER M4 ;
        RECT  0 39.456 0.084 39.48 ;
    END
  END src[93]
  PIN src[94]
    DIRECTION INPUT ;
    USE SIGNAL ;
    PORT
      LAYER M4 ;
        RECT  0 39.792 0.084 39.816 ;
    END
  END src[94]
  PIN src[95]
    DIRECTION INPUT ;
    USE SIGNAL ;
    PORT
      LAYER M6 ;
        RECT  0 40.064 0.07 40.096 ;
    END
  END src[95]
  PIN src[96]
    DIRECTION INPUT ;
    USE SIGNAL ;
    PORT
      LAYER M6 ;
        RECT  0 40.384 0.07 40.416 ;
    END
  END src[96]
  PIN src[97]
    DIRECTION INPUT ;
    USE SIGNAL ;
    PORT
      LAYER M6 ;
        RECT  0 40.704 0.07 40.736 ;
    END
  END src[97]
  PIN src[98]
    DIRECTION INPUT ;
    USE SIGNAL ;
    PORT
      LAYER M6 ;
        RECT  0 41.024 0.07 41.056 ;
    END
  END src[98]
  PIN src[99]
    DIRECTION INPUT ;
    USE SIGNAL ;
    PORT
      LAYER M6 ;
        RECT  0 41.344 0.07 41.376 ;
    END
  END src[99]
  PIN src[9]
    DIRECTION INPUT ;
    USE SIGNAL ;
    PORT
      LAYER M4 ;
        RECT  0 13.248 0.084 13.272 ;
    END
  END src[9]
  PIN sum[0]
    DIRECTION OUTPUT ;
    USE SIGNAL ;
    PORT
      LAYER M4 ;
        RECT  179.916 31.392 180 31.416 ;
    END
  END sum[0]
  PIN sum[100]
    DIRECTION OUTPUT ;
    USE SIGNAL ;
    PORT
      LAYER M6 ;
        RECT  179.93 123.648 180 123.68 ;
    END
  END sum[100]
  PIN sum[101]
    DIRECTION OUTPUT ;
    USE SIGNAL ;
    PORT
      LAYER M6 ;
        RECT  179.93 124.608 180 124.64 ;
    END
  END sum[101]
  PIN sum[102]
    DIRECTION OUTPUT ;
    USE SIGNAL ;
    PORT
      LAYER M6 ;
        RECT  179.93 125.504 180 125.536 ;
    END
  END sum[102]
  PIN sum[103]
    DIRECTION OUTPUT ;
    USE SIGNAL ;
    PORT
      LAYER M6 ;
        RECT  179.93 126.464 180 126.496 ;
    END
  END sum[103]
  PIN sum[104]
    DIRECTION OUTPUT ;
    USE SIGNAL ;
    PORT
      LAYER M6 ;
        RECT  179.93 127.36 180 127.392 ;
    END
  END sum[104]
  PIN sum[105]
    DIRECTION OUTPUT ;
    USE SIGNAL ;
    PORT
      LAYER M6 ;
        RECT  179.93 128.32 180 128.352 ;
    END
  END sum[105]
  PIN sum[106]
    DIRECTION OUTPUT ;
    USE SIGNAL ;
    PORT
      LAYER M6 ;
        RECT  179.93 129.216 180 129.248 ;
    END
  END sum[106]
  PIN sum[107]
    DIRECTION OUTPUT ;
    USE SIGNAL ;
    PORT
      LAYER M6 ;
        RECT  179.93 130.112 180 130.144 ;
    END
  END sum[107]
  PIN sum[108]
    DIRECTION OUTPUT ;
    USE SIGNAL ;
    PORT
      LAYER M6 ;
        RECT  179.93 131.072 180 131.104 ;
    END
  END sum[108]
  PIN sum[109]
    DIRECTION OUTPUT ;
    USE SIGNAL ;
    PORT
      LAYER M6 ;
        RECT  179.93 131.968 180 132 ;
    END
  END sum[109]
  PIN sum[10]
    DIRECTION OUTPUT ;
    USE SIGNAL ;
    PORT
      LAYER M4 ;
        RECT  179.916 40.608 180 40.632 ;
    END
  END sum[10]
  PIN sum[110]
    DIRECTION OUTPUT ;
    USE SIGNAL ;
    PORT
      LAYER M6 ;
        RECT  179.93 132.928 180 132.96 ;
    END
  END sum[110]
  PIN sum[111]
    DIRECTION OUTPUT ;
    USE SIGNAL ;
    PORT
      LAYER M6 ;
        RECT  179.93 133.824 180 133.856 ;
    END
  END sum[111]
  PIN sum[112]
    DIRECTION OUTPUT ;
    USE SIGNAL ;
    PORT
      LAYER M6 ;
        RECT  179.93 134.784 180 134.816 ;
    END
  END sum[112]
  PIN sum[113]
    DIRECTION OUTPUT ;
    USE SIGNAL ;
    PORT
      LAYER M6 ;
        RECT  179.93 135.68 180 135.712 ;
    END
  END sum[113]
  PIN sum[114]
    DIRECTION OUTPUT ;
    USE SIGNAL ;
    PORT
      LAYER M6 ;
        RECT  179.93 136.576 180 136.608 ;
    END
  END sum[114]
  PIN sum[115]
    DIRECTION OUTPUT ;
    USE SIGNAL ;
    PORT
      LAYER M6 ;
        RECT  179.93 137.536 180 137.568 ;
    END
  END sum[115]
  PIN sum[116]
    DIRECTION OUTPUT ;
    USE SIGNAL ;
    PORT
      LAYER M6 ;
        RECT  179.93 138.432 180 138.464 ;
    END
  END sum[116]
  PIN sum[117]
    DIRECTION OUTPUT ;
    USE SIGNAL ;
    PORT
      LAYER M6 ;
        RECT  179.93 139.392 180 139.424 ;
    END
  END sum[117]
  PIN sum[118]
    DIRECTION OUTPUT ;
    USE SIGNAL ;
    PORT
      LAYER M6 ;
        RECT  179.93 140.288 180 140.32 ;
    END
  END sum[118]
  PIN sum[119]
    DIRECTION OUTPUT ;
    USE SIGNAL ;
    PORT
      LAYER M6 ;
        RECT  179.93 141.184 180 141.216 ;
    END
  END sum[119]
  PIN sum[11]
    DIRECTION OUTPUT ;
    USE SIGNAL ;
    PORT
      LAYER M4 ;
        RECT  179.916 41.52 180 41.544 ;
    END
  END sum[11]
  PIN sum[120]
    DIRECTION OUTPUT ;
    USE SIGNAL ;
    PORT
      LAYER M6 ;
        RECT  179.93 142.144 180 142.176 ;
    END
  END sum[120]
  PIN sum[121]
    DIRECTION OUTPUT ;
    USE SIGNAL ;
    PORT
      LAYER M6 ;
        RECT  179.93 143.04 180 143.072 ;
    END
  END sum[121]
  PIN sum[122]
    DIRECTION OUTPUT ;
    USE SIGNAL ;
    PORT
      LAYER M6 ;
        RECT  179.93 144 180 144.032 ;
    END
  END sum[122]
  PIN sum[123]
    DIRECTION OUTPUT ;
    USE SIGNAL ;
    PORT
      LAYER M6 ;
        RECT  179.93 144.896 180 144.928 ;
    END
  END sum[123]
  PIN sum[124]
    DIRECTION OUTPUT ;
    USE SIGNAL ;
    PORT
      LAYER M6 ;
        RECT  179.93 145.856 180 145.888 ;
    END
  END sum[124]
  PIN sum[125]
    DIRECTION OUTPUT ;
    USE SIGNAL ;
    PORT
      LAYER M6 ;
        RECT  179.93 146.752 180 146.784 ;
    END
  END sum[125]
  PIN sum[126]
    DIRECTION OUTPUT ;
    USE SIGNAL ;
    PORT
      LAYER M6 ;
        RECT  179.93 147.648 180 147.68 ;
    END
  END sum[126]
  PIN sum[127]
    DIRECTION OUTPUT ;
    USE SIGNAL ;
    PORT
      LAYER M4 ;
        RECT  179.916 148.608 180 148.632 ;
    END
  END sum[127]
  PIN sum[12]
    DIRECTION OUTPUT ;
    USE SIGNAL ;
    PORT
      LAYER M4 ;
        RECT  179.916 42.432 180 42.456 ;
    END
  END sum[12]
  PIN sum[13]
    DIRECTION OUTPUT ;
    USE SIGNAL ;
    PORT
      LAYER M4 ;
        RECT  179.916 43.392 180 43.416 ;
    END
  END sum[13]
  PIN sum[14]
    DIRECTION OUTPUT ;
    USE SIGNAL ;
    PORT
      LAYER M4 ;
        RECT  179.916 44.304 180 44.328 ;
    END
  END sum[14]
  PIN sum[15]
    DIRECTION OUTPUT ;
    USE SIGNAL ;
    PORT
      LAYER M4 ;
        RECT  179.916 45.216 180 45.24 ;
    END
  END sum[15]
  PIN sum[16]
    DIRECTION OUTPUT ;
    USE SIGNAL ;
    PORT
      LAYER M4 ;
        RECT  179.916 46.128 180 46.152 ;
    END
  END sum[16]
  PIN sum[17]
    DIRECTION OUTPUT ;
    USE SIGNAL ;
    PORT
      LAYER M4 ;
        RECT  179.916 47.088 180 47.112 ;
    END
  END sum[17]
  PIN sum[18]
    DIRECTION OUTPUT ;
    USE SIGNAL ;
    PORT
      LAYER M4 ;
        RECT  179.916 48 180 48.024 ;
    END
  END sum[18]
  PIN sum[19]
    DIRECTION OUTPUT ;
    USE SIGNAL ;
    PORT
      LAYER M4 ;
        RECT  179.916 48.912 180 48.936 ;
    END
  END sum[19]
  PIN sum[1]
    DIRECTION OUTPUT ;
    USE SIGNAL ;
    PORT
      LAYER M4 ;
        RECT  179.916 32.304 180 32.328 ;
    END
  END sum[1]
  PIN sum[20]
    DIRECTION OUTPUT ;
    USE SIGNAL ;
    PORT
      LAYER M4 ;
        RECT  179.916 49.824 180 49.848 ;
    END
  END sum[20]
  PIN sum[21]
    DIRECTION OUTPUT ;
    USE SIGNAL ;
    PORT
      LAYER M4 ;
        RECT  179.916 50.736 180 50.76 ;
    END
  END sum[21]
  PIN sum[22]
    DIRECTION OUTPUT ;
    USE SIGNAL ;
    PORT
      LAYER M4 ;
        RECT  179.916 51.696 180 51.72 ;
    END
  END sum[22]
  PIN sum[23]
    DIRECTION OUTPUT ;
    USE SIGNAL ;
    PORT
      LAYER M4 ;
        RECT  179.916 52.608 180 52.632 ;
    END
  END sum[23]
  PIN sum[24]
    DIRECTION OUTPUT ;
    USE SIGNAL ;
    PORT
      LAYER M4 ;
        RECT  179.916 53.52 180 53.544 ;
    END
  END sum[24]
  PIN sum[25]
    DIRECTION OUTPUT ;
    USE SIGNAL ;
    PORT
      LAYER M4 ;
        RECT  179.916 54.432 180 54.456 ;
    END
  END sum[25]
  PIN sum[26]
    DIRECTION OUTPUT ;
    USE SIGNAL ;
    PORT
      LAYER M4 ;
        RECT  179.916 55.392 180 55.416 ;
    END
  END sum[26]
  PIN sum[27]
    DIRECTION OUTPUT ;
    USE SIGNAL ;
    PORT
      LAYER M4 ;
        RECT  179.916 56.304 180 56.328 ;
    END
  END sum[27]
  PIN sum[28]
    DIRECTION OUTPUT ;
    USE SIGNAL ;
    PORT
      LAYER M4 ;
        RECT  179.916 57.216 180 57.24 ;
    END
  END sum[28]
  PIN sum[29]
    DIRECTION OUTPUT ;
    USE SIGNAL ;
    PORT
      LAYER M4 ;
        RECT  179.916 58.128 180 58.152 ;
    END
  END sum[29]
  PIN sum[2]
    DIRECTION OUTPUT ;
    USE SIGNAL ;
    PORT
      LAYER M4 ;
        RECT  179.916 33.216 180 33.24 ;
    END
  END sum[2]
  PIN sum[30]
    DIRECTION OUTPUT ;
    USE SIGNAL ;
    PORT
      LAYER M4 ;
        RECT  179.916 59.088 180 59.112 ;
    END
  END sum[30]
  PIN sum[31]
    DIRECTION OUTPUT ;
    USE SIGNAL ;
    PORT
      LAYER M6 ;
        RECT  179.93 59.968 180 60 ;
    END
  END sum[31]
  PIN sum[32]
    DIRECTION OUTPUT ;
    USE SIGNAL ;
    PORT
      LAYER M6 ;
        RECT  179.93 60.928 180 60.96 ;
    END
  END sum[32]
  PIN sum[33]
    DIRECTION OUTPUT ;
    USE SIGNAL ;
    PORT
      LAYER M6 ;
        RECT  179.93 61.824 180 61.856 ;
    END
  END sum[33]
  PIN sum[34]
    DIRECTION OUTPUT ;
    USE SIGNAL ;
    PORT
      LAYER M6 ;
        RECT  179.93 62.784 180 62.816 ;
    END
  END sum[34]
  PIN sum[35]
    DIRECTION OUTPUT ;
    USE SIGNAL ;
    PORT
      LAYER M6 ;
        RECT  179.93 63.68 180 63.712 ;
    END
  END sum[35]
  PIN sum[36]
    DIRECTION OUTPUT ;
    USE SIGNAL ;
    PORT
      LAYER M6 ;
        RECT  179.93 64.576 180 64.608 ;
    END
  END sum[36]
  PIN sum[37]
    DIRECTION OUTPUT ;
    USE SIGNAL ;
    PORT
      LAYER M6 ;
        RECT  179.93 65.536 180 65.568 ;
    END
  END sum[37]
  PIN sum[38]
    DIRECTION OUTPUT ;
    USE SIGNAL ;
    PORT
      LAYER M6 ;
        RECT  179.93 66.432 180 66.464 ;
    END
  END sum[38]
  PIN sum[39]
    DIRECTION OUTPUT ;
    USE SIGNAL ;
    PORT
      LAYER M6 ;
        RECT  179.93 67.392 180 67.424 ;
    END
  END sum[39]
  PIN sum[3]
    DIRECTION OUTPUT ;
    USE SIGNAL ;
    PORT
      LAYER M4 ;
        RECT  179.916 34.128 180 34.152 ;
    END
  END sum[3]
  PIN sum[40]
    DIRECTION OUTPUT ;
    USE SIGNAL ;
    PORT
      LAYER M6 ;
        RECT  179.93 68.288 180 68.32 ;
    END
  END sum[40]
  PIN sum[41]
    DIRECTION OUTPUT ;
    USE SIGNAL ;
    PORT
      LAYER M6 ;
        RECT  179.93 69.184 180 69.216 ;
    END
  END sum[41]
  PIN sum[42]
    DIRECTION OUTPUT ;
    USE SIGNAL ;
    PORT
      LAYER M6 ;
        RECT  179.93 70.144 180 70.176 ;
    END
  END sum[42]
  PIN sum[43]
    DIRECTION OUTPUT ;
    USE SIGNAL ;
    PORT
      LAYER M6 ;
        RECT  179.93 71.04 180 71.072 ;
    END
  END sum[43]
  PIN sum[44]
    DIRECTION OUTPUT ;
    USE SIGNAL ;
    PORT
      LAYER M6 ;
        RECT  179.93 72 180 72.032 ;
    END
  END sum[44]
  PIN sum[45]
    DIRECTION OUTPUT ;
    USE SIGNAL ;
    PORT
      LAYER M6 ;
        RECT  179.93 72.896 180 72.928 ;
    END
  END sum[45]
  PIN sum[46]
    DIRECTION OUTPUT ;
    USE SIGNAL ;
    PORT
      LAYER M6 ;
        RECT  179.93 73.856 180 73.888 ;
    END
  END sum[46]
  PIN sum[47]
    DIRECTION OUTPUT ;
    USE SIGNAL ;
    PORT
      LAYER M6 ;
        RECT  179.93 74.752 180 74.784 ;
    END
  END sum[47]
  PIN sum[48]
    DIRECTION OUTPUT ;
    USE SIGNAL ;
    PORT
      LAYER M6 ;
        RECT  179.93 75.648 180 75.68 ;
    END
  END sum[48]
  PIN sum[49]
    DIRECTION OUTPUT ;
    USE SIGNAL ;
    PORT
      LAYER M6 ;
        RECT  179.93 76.608 180 76.64 ;
    END
  END sum[49]
  PIN sum[4]
    DIRECTION OUTPUT ;
    USE SIGNAL ;
    PORT
      LAYER M4 ;
        RECT  179.916 35.088 180 35.112 ;
    END
  END sum[4]
  PIN sum[50]
    DIRECTION OUTPUT ;
    USE SIGNAL ;
    PORT
      LAYER M6 ;
        RECT  179.93 77.504 180 77.536 ;
    END
  END sum[50]
  PIN sum[51]
    DIRECTION OUTPUT ;
    USE SIGNAL ;
    PORT
      LAYER M6 ;
        RECT  179.93 78.464 180 78.496 ;
    END
  END sum[51]
  PIN sum[52]
    DIRECTION OUTPUT ;
    USE SIGNAL ;
    PORT
      LAYER M6 ;
        RECT  179.93 79.36 180 79.392 ;
    END
  END sum[52]
  PIN sum[53]
    DIRECTION OUTPUT ;
    USE SIGNAL ;
    PORT
      LAYER M6 ;
        RECT  179.93 80.32 180 80.352 ;
    END
  END sum[53]
  PIN sum[54]
    DIRECTION OUTPUT ;
    USE SIGNAL ;
    PORT
      LAYER M6 ;
        RECT  179.93 81.216 180 81.248 ;
    END
  END sum[54]
  PIN sum[55]
    DIRECTION OUTPUT ;
    USE SIGNAL ;
    PORT
      LAYER M6 ;
        RECT  179.93 82.112 180 82.144 ;
    END
  END sum[55]
  PIN sum[56]
    DIRECTION OUTPUT ;
    USE SIGNAL ;
    PORT
      LAYER M6 ;
        RECT  179.93 83.072 180 83.104 ;
    END
  END sum[56]
  PIN sum[57]
    DIRECTION OUTPUT ;
    USE SIGNAL ;
    PORT
      LAYER M6 ;
        RECT  179.93 83.968 180 84 ;
    END
  END sum[57]
  PIN sum[58]
    DIRECTION OUTPUT ;
    USE SIGNAL ;
    PORT
      LAYER M6 ;
        RECT  179.93 84.928 180 84.96 ;
    END
  END sum[58]
  PIN sum[59]
    DIRECTION OUTPUT ;
    USE SIGNAL ;
    PORT
      LAYER M6 ;
        RECT  179.93 85.824 180 85.856 ;
    END
  END sum[59]
  PIN sum[5]
    DIRECTION OUTPUT ;
    USE SIGNAL ;
    PORT
      LAYER M4 ;
        RECT  179.916 36 180 36.024 ;
    END
  END sum[5]
  PIN sum[60]
    DIRECTION OUTPUT ;
    USE SIGNAL ;
    PORT
      LAYER M6 ;
        RECT  179.93 86.784 180 86.816 ;
    END
  END sum[60]
  PIN sum[61]
    DIRECTION OUTPUT ;
    USE SIGNAL ;
    PORT
      LAYER M6 ;
        RECT  179.93 87.68 180 87.712 ;
    END
  END sum[61]
  PIN sum[62]
    DIRECTION OUTPUT ;
    USE SIGNAL ;
    PORT
      LAYER M6 ;
        RECT  179.93 88.576 180 88.608 ;
    END
  END sum[62]
  PIN sum[63]
    DIRECTION OUTPUT ;
    USE SIGNAL ;
    PORT
      LAYER M4 ;
        RECT  179.916 89.52 180 89.544 ;
    END
  END sum[63]
  PIN sum[64]
    DIRECTION OUTPUT ;
    USE SIGNAL ;
    PORT
      LAYER M4 ;
        RECT  179.916 90.432 180 90.456 ;
    END
  END sum[64]
  PIN sum[65]
    DIRECTION OUTPUT ;
    USE SIGNAL ;
    PORT
      LAYER M4 ;
        RECT  179.916 91.392 180 91.416 ;
    END
  END sum[65]
  PIN sum[66]
    DIRECTION OUTPUT ;
    USE SIGNAL ;
    PORT
      LAYER M4 ;
        RECT  179.916 92.304 180 92.328 ;
    END
  END sum[66]
  PIN sum[67]
    DIRECTION OUTPUT ;
    USE SIGNAL ;
    PORT
      LAYER M4 ;
        RECT  179.916 93.216 180 93.24 ;
    END
  END sum[67]
  PIN sum[68]
    DIRECTION OUTPUT ;
    USE SIGNAL ;
    PORT
      LAYER M4 ;
        RECT  179.916 94.128 180 94.152 ;
    END
  END sum[68]
  PIN sum[69]
    DIRECTION OUTPUT ;
    USE SIGNAL ;
    PORT
      LAYER M4 ;
        RECT  179.916 95.088 180 95.112 ;
    END
  END sum[69]
  PIN sum[6]
    DIRECTION OUTPUT ;
    USE SIGNAL ;
    PORT
      LAYER M4 ;
        RECT  179.916 36.912 180 36.936 ;
    END
  END sum[6]
  PIN sum[70]
    DIRECTION OUTPUT ;
    USE SIGNAL ;
    PORT
      LAYER M4 ;
        RECT  179.916 96 180 96.024 ;
    END
  END sum[70]
  PIN sum[71]
    DIRECTION OUTPUT ;
    USE SIGNAL ;
    PORT
      LAYER M4 ;
        RECT  179.916 96.912 180 96.936 ;
    END
  END sum[71]
  PIN sum[72]
    DIRECTION OUTPUT ;
    USE SIGNAL ;
    PORT
      LAYER M4 ;
        RECT  179.916 97.824 180 97.848 ;
    END
  END sum[72]
  PIN sum[73]
    DIRECTION OUTPUT ;
    USE SIGNAL ;
    PORT
      LAYER M4 ;
        RECT  179.916 98.736 180 98.76 ;
    END
  END sum[73]
  PIN sum[74]
    DIRECTION OUTPUT ;
    USE SIGNAL ;
    PORT
      LAYER M4 ;
        RECT  179.916 99.696 180 99.72 ;
    END
  END sum[74]
  PIN sum[75]
    DIRECTION OUTPUT ;
    USE SIGNAL ;
    PORT
      LAYER M4 ;
        RECT  179.916 100.608 180 100.632 ;
    END
  END sum[75]
  PIN sum[76]
    DIRECTION OUTPUT ;
    USE SIGNAL ;
    PORT
      LAYER M4 ;
        RECT  179.916 101.52 180 101.544 ;
    END
  END sum[76]
  PIN sum[77]
    DIRECTION OUTPUT ;
    USE SIGNAL ;
    PORT
      LAYER M4 ;
        RECT  179.916 102.432 180 102.456 ;
    END
  END sum[77]
  PIN sum[78]
    DIRECTION OUTPUT ;
    USE SIGNAL ;
    PORT
      LAYER M4 ;
        RECT  179.916 103.392 180 103.416 ;
    END
  END sum[78]
  PIN sum[79]
    DIRECTION OUTPUT ;
    USE SIGNAL ;
    PORT
      LAYER M4 ;
        RECT  179.916 104.304 180 104.328 ;
    END
  END sum[79]
  PIN sum[7]
    DIRECTION OUTPUT ;
    USE SIGNAL ;
    PORT
      LAYER M4 ;
        RECT  179.916 37.824 180 37.848 ;
    END
  END sum[7]
  PIN sum[80]
    DIRECTION OUTPUT ;
    USE SIGNAL ;
    PORT
      LAYER M4 ;
        RECT  179.916 105.216 180 105.24 ;
    END
  END sum[80]
  PIN sum[81]
    DIRECTION OUTPUT ;
    USE SIGNAL ;
    PORT
      LAYER M4 ;
        RECT  179.916 106.128 180 106.152 ;
    END
  END sum[81]
  PIN sum[82]
    DIRECTION OUTPUT ;
    USE SIGNAL ;
    PORT
      LAYER M4 ;
        RECT  179.916 107.088 180 107.112 ;
    END
  END sum[82]
  PIN sum[83]
    DIRECTION OUTPUT ;
    USE SIGNAL ;
    PORT
      LAYER M4 ;
        RECT  179.916 108 180 108.024 ;
    END
  END sum[83]
  PIN sum[84]
    DIRECTION OUTPUT ;
    USE SIGNAL ;
    PORT
      LAYER M4 ;
        RECT  179.916 108.912 180 108.936 ;
    END
  END sum[84]
  PIN sum[85]
    DIRECTION OUTPUT ;
    USE SIGNAL ;
    PORT
      LAYER M4 ;
        RECT  179.916 109.824 180 109.848 ;
    END
  END sum[85]
  PIN sum[86]
    DIRECTION OUTPUT ;
    USE SIGNAL ;
    PORT
      LAYER M4 ;
        RECT  179.916 110.736 180 110.76 ;
    END
  END sum[86]
  PIN sum[87]
    DIRECTION OUTPUT ;
    USE SIGNAL ;
    PORT
      LAYER M4 ;
        RECT  179.916 111.696 180 111.72 ;
    END
  END sum[87]
  PIN sum[88]
    DIRECTION OUTPUT ;
    USE SIGNAL ;
    PORT
      LAYER M4 ;
        RECT  179.916 112.608 180 112.632 ;
    END
  END sum[88]
  PIN sum[89]
    DIRECTION OUTPUT ;
    USE SIGNAL ;
    PORT
      LAYER M4 ;
        RECT  179.916 113.52 180 113.544 ;
    END
  END sum[89]
  PIN sum[8]
    DIRECTION OUTPUT ;
    USE SIGNAL ;
    PORT
      LAYER M4 ;
        RECT  179.916 38.736 180 38.76 ;
    END
  END sum[8]
  PIN sum[90]
    DIRECTION OUTPUT ;
    USE SIGNAL ;
    PORT
      LAYER M4 ;
        RECT  179.916 114.432 180 114.456 ;
    END
  END sum[90]
  PIN sum[91]
    DIRECTION OUTPUT ;
    USE SIGNAL ;
    PORT
      LAYER M4 ;
        RECT  179.916 115.392 180 115.416 ;
    END
  END sum[91]
  PIN sum[92]
    DIRECTION OUTPUT ;
    USE SIGNAL ;
    PORT
      LAYER M4 ;
        RECT  179.916 116.304 180 116.328 ;
    END
  END sum[92]
  PIN sum[93]
    DIRECTION OUTPUT ;
    USE SIGNAL ;
    PORT
      LAYER M4 ;
        RECT  179.916 117.216 180 117.24 ;
    END
  END sum[93]
  PIN sum[94]
    DIRECTION OUTPUT ;
    USE SIGNAL ;
    PORT
      LAYER M4 ;
        RECT  179.916 118.128 180 118.152 ;
    END
  END sum[94]
  PIN sum[95]
    DIRECTION OUTPUT ;
    USE SIGNAL ;
    PORT
      LAYER M6 ;
        RECT  179.93 119.04 180 119.072 ;
    END
  END sum[95]
  PIN sum[96]
    DIRECTION OUTPUT ;
    USE SIGNAL ;
    PORT
      LAYER M6 ;
        RECT  179.93 120 180 120.032 ;
    END
  END sum[96]
  PIN sum[97]
    DIRECTION OUTPUT ;
    USE SIGNAL ;
    PORT
      LAYER M6 ;
        RECT  179.93 120.896 180 120.928 ;
    END
  END sum[97]
  PIN sum[98]
    DIRECTION OUTPUT ;
    USE SIGNAL ;
    PORT
      LAYER M6 ;
        RECT  179.93 121.856 180 121.888 ;
    END
  END sum[98]
  PIN sum[99]
    DIRECTION OUTPUT ;
    USE SIGNAL ;
    PORT
      LAYER M6 ;
        RECT  179.93 122.752 180 122.784 ;
    END
  END sum[99]
  PIN sum[9]
    DIRECTION OUTPUT ;
    USE SIGNAL ;
    PORT
      LAYER M4 ;
        RECT  179.916 39.696 180 39.72 ;
    END
  END sum[9]
  PIN v_out
    DIRECTION OUTPUT ;
    USE SIGNAL ;
    PORT
      LAYER M4 ;
        RECT  179.916 149.52 180 149.544 ;
    END
  END v_out
  PIN VSS
    DIRECTION INOUT ;
    USE GROUND ;
    PORT
      LAYER M6 ;
        RECT  2.16 175.329 177.822 175.617 ;
        RECT  2.16 169.929 177.822 170.217 ;
        RECT  2.16 164.529 177.822 164.817 ;
        RECT  2.16 159.129 177.822 159.417 ;
        RECT  2.16 153.729 177.822 154.017 ;
        RECT  2.16 148.329 177.822 148.617 ;
        RECT  2.16 142.929 177.822 143.217 ;
        RECT  2.16 137.529 177.822 137.817 ;
        RECT  2.16 132.129 177.822 132.417 ;
        RECT  2.16 126.729 177.822 127.017 ;
        RECT  2.16 121.329 177.822 121.617 ;
        RECT  2.16 115.929 177.822 116.217 ;
        RECT  2.16 110.529 177.822 110.817 ;
        RECT  2.16 105.129 177.822 105.417 ;
        RECT  2.16 99.729 177.822 100.017 ;
        RECT  2.16 94.329 177.822 94.617 ;
        RECT  2.16 88.929 177.822 89.217 ;
        RECT  2.16 83.529 177.822 83.817 ;
        RECT  2.16 78.129 177.822 78.417 ;
        RECT  2.16 72.729 177.822 73.017 ;
        RECT  2.16 67.329 177.822 67.617 ;
        RECT  2.16 61.929 177.822 62.217 ;
        RECT  2.16 56.529 177.822 56.817 ;
        RECT  2.16 51.129 177.822 51.417 ;
        RECT  2.16 45.729 177.822 46.017 ;
        RECT  2.16 40.329 177.822 40.617 ;
        RECT  2.16 34.929 177.822 35.217 ;
        RECT  2.16 29.529 177.822 29.817 ;
        RECT  2.16 24.129 177.822 24.417 ;
        RECT  2.16 18.729 177.822 19.017 ;
        RECT  2.16 13.329 177.822 13.617 ;
        RECT  2.16 7.929 177.822 8.217 ;
        RECT  2.16 2.529 177.822 2.817 ;
    END
  END VSS
  PIN VDD
    DIRECTION INOUT ;
    USE POWER ;
    PORT
      LAYER M6 ;
        RECT  2.16 175.713 177.822 176.001 ;
        RECT  2.16 170.313 177.822 170.601 ;
        RECT  2.16 164.913 177.822 165.201 ;
        RECT  2.16 159.513 177.822 159.801 ;
        RECT  2.16 154.113 177.822 154.401 ;
        RECT  2.16 148.713 177.822 149.001 ;
        RECT  2.16 143.313 177.822 143.601 ;
        RECT  2.16 137.913 177.822 138.201 ;
        RECT  2.16 132.513 177.822 132.801 ;
        RECT  2.16 127.113 177.822 127.401 ;
        RECT  2.16 121.713 177.822 122.001 ;
        RECT  2.16 116.313 177.822 116.601 ;
        RECT  2.16 110.913 177.822 111.201 ;
        RECT  2.16 105.513 177.822 105.801 ;
        RECT  2.16 100.113 177.822 100.401 ;
        RECT  2.16 94.713 177.822 95.001 ;
        RECT  2.16 89.313 177.822 89.601 ;
        RECT  2.16 83.913 177.822 84.201 ;
        RECT  2.16 78.513 177.822 78.801 ;
        RECT  2.16 73.113 177.822 73.401 ;
        RECT  2.16 67.713 177.822 68.001 ;
        RECT  2.16 62.313 177.822 62.601 ;
        RECT  2.16 56.913 177.822 57.201 ;
        RECT  2.16 51.513 177.822 51.801 ;
        RECT  2.16 46.113 177.822 46.401 ;
        RECT  2.16 40.713 177.822 41.001 ;
        RECT  2.16 35.313 177.822 35.601 ;
        RECT  2.16 29.913 177.822 30.201 ;
        RECT  2.16 24.513 177.822 24.801 ;
        RECT  2.16 19.113 177.822 19.401 ;
        RECT  2.16 13.713 177.822 14.001 ;
        RECT  2.16 8.313 177.822 8.601 ;
        RECT  2.16 2.913 177.822 3.201 ;
    END
  END VDD
  OBS
    LAYER RVTN ;
     RECT  0 2.137 180 180 ;
    LAYER RVTP ;
     RECT  0 2.137 180 180 ;
    LAYER M1 ;
     RECT  0 2.137 180 180 ;
    LAYER M2 ;
     RECT  0 2.137 180 180 ;
    LAYER M3 ;
     RECT  0 2.137 180 180 ;
    LAYER M4 ;
     RECT  0 2.137 180 180 ;
    LAYER M5 ;
     RECT  0 2.137 180 180 ;
    LAYER M6 ;
     RECT  0 2.137 180 180 ;
    LAYER M7 ;
     RECT  0 2.137 180 180 ;
  END
END ot_coll_fold_slice
END LIBRARY
